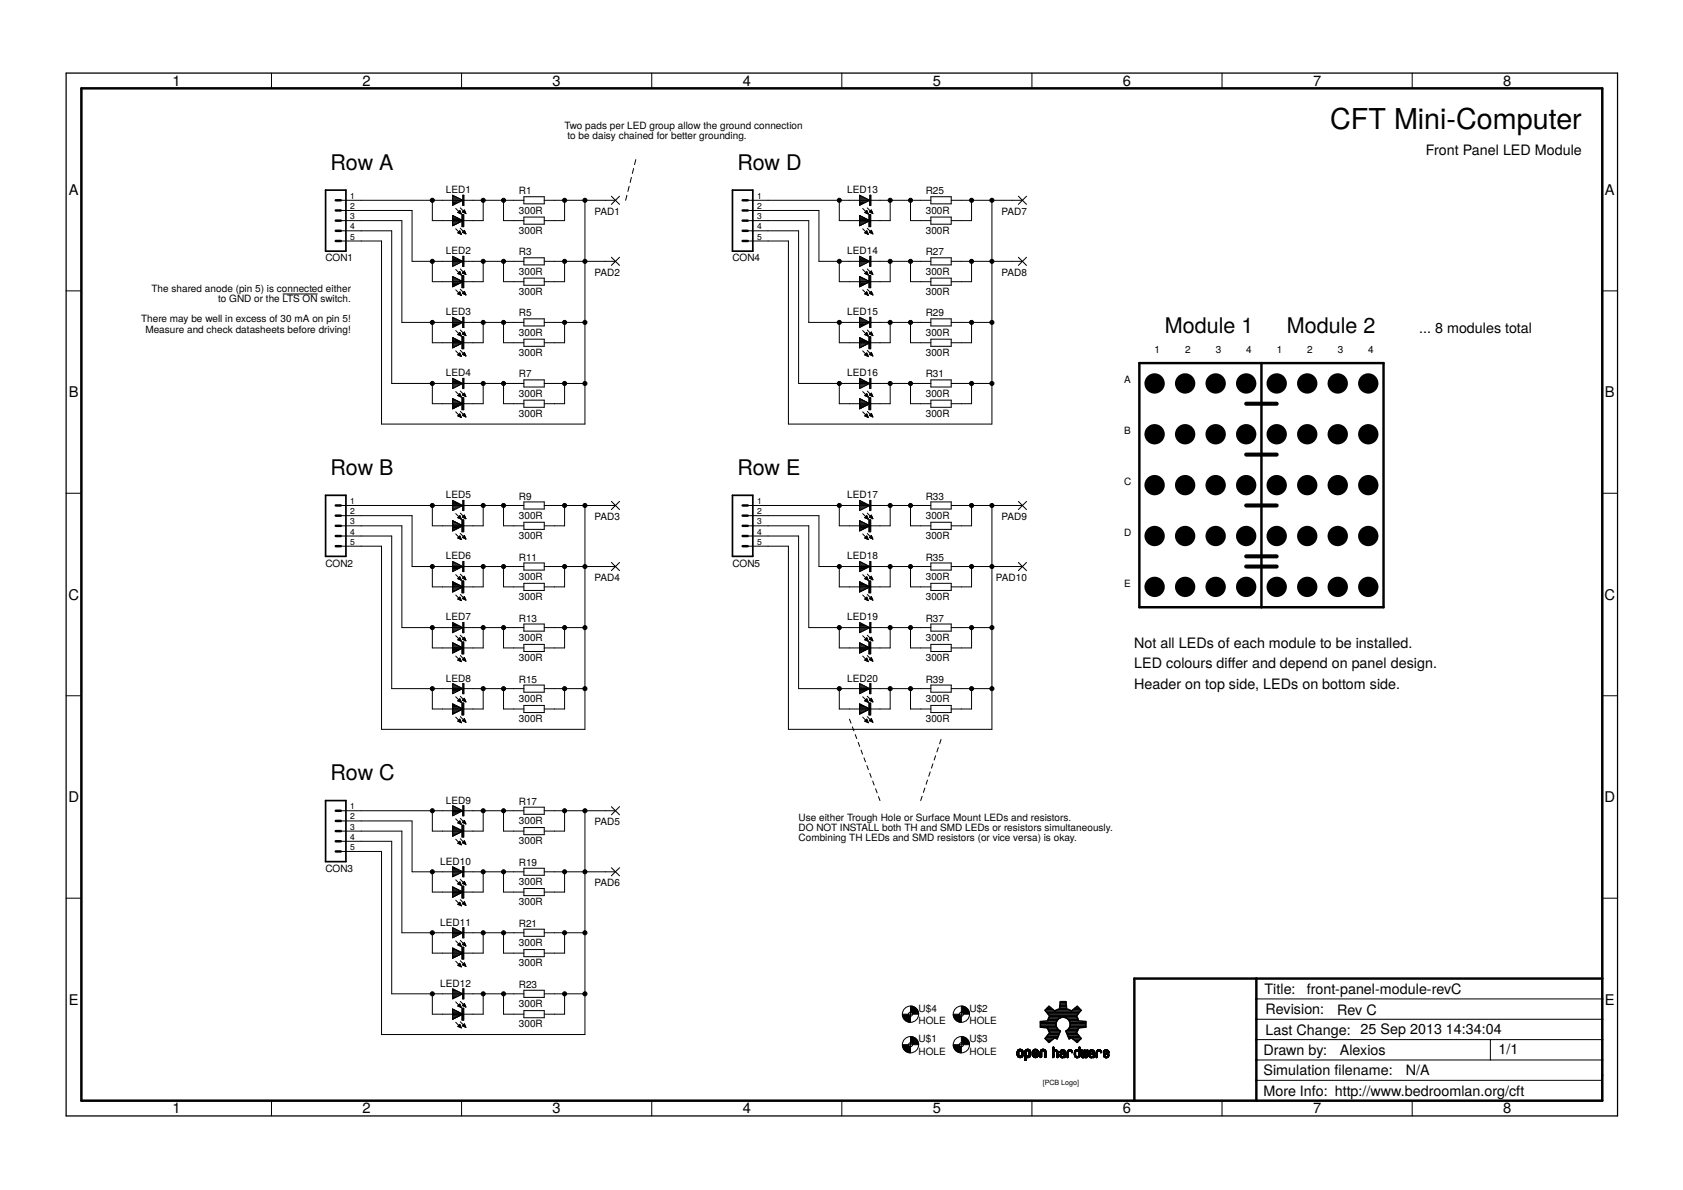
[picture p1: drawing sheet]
<svg xmlns="http://www.w3.org/2000/svg" width="420mm" height="297mm" viewBox="0 0 420 297" stroke-linecap="round" stroke-linejoin="round" font-family="sans-serif">
<defs><g id="words">
<text font-size="7.2" x="332.1" y="32.2">CFT Mini-Computer</text>
<g font-size="5.4">
<text x="82.5" y="42.4">Row A</text>
<text x="184.1" y="42.4">Row D</text>
<text x="290.8" y="83">Module 1</text>
<text x="321.3" y="83">Module 2</text>
<text x="82.5" y="118.6">Row B</text>
<text x="184.1" y="118.6">Row E</text>
<text x="82.5" y="194.7">Row C</text>
</g>
<g font-size="3.7">
<text x="43" y="21.4">1</text>
<text x="90.5" y="21.4">2</text>
<text x="138" y="21.4">3</text>
<text x="185.4" y="21.4">4</text>
<text x="232.9" y="21.4">5</text>
<text x="280.3" y="21.4">6</text>
<text x="327.8" y="21.4">7</text>
<text x="375.3" y="21.4">8</text>
<text x="17.2" y="48.6">A</text>
<text x="400.7" y="48.6">A</text>
<text x="17.2" y="99.2">B</text>
<text x="400.7" y="99.2">B</text>
<text x="17.1" y="149.7">C</text>
<text x="400.6" y="149.7">C</text>
<text x="17.1" y="200.2">D</text>
<text x="400.6" y="200.2">D</text>
<text x="17.2" y="250.8">E</text>
<text x="400.7" y="250.8">E</text>
<text x="43" y="277.9">1</text>
<text x="90.5" y="277.9">2</text>
<text x="138" y="277.9">3</text>
<text x="185.4" y="277.9">4</text>
<text x="232.9" y="277.9">5</text>
<text x="280.3" y="277.9">6</text>
<text x="327.8" y="277.9">7</text>
<text x="375.3" y="277.9">8</text>
</g>
<g font-size="3.6">
<text x="356" y="38.6">Front Panel LED Module</text>
<text x="354.3" y="83">... 8 modules total</text>
<text x="283.2" y="161.7">Not all LEDs of each module to be installed.</text>
<text x="283.2" y="166.8">LED colours difer and depend on panel design.</text>
<text x="306.5" y="166.8">f</text>
<text x="283.2" y="171.9">Header on top side, LEDs on bottom side.</text>
<text x="315.7" y="248.1">Title:</text>
<text x="326.2" y="248.2">front-panel-module-revC</text>
<text x="315.9" y="253.2">Revision:</text>
<text x="333.8" y="253.3">Rev C</text>
<text x="315.4" y="263.3">Drawn by:</text>
<text x="315.9" y="258.2">Last Change: 25 Sep 2013</text>
<text x="334.5" y="263.3">Alexios</text>
<text x="361" y="258.1">14:34:04</text>
<text x="374.1" y="263.2">1/1</text>
<text x="315.4" y="268.4">Simulation flename:</text>
<text x="333.2" y="268.4">i</text>
<text x="351" y="268.4">N/A</text>
<text x="315.4" y="273.5">More Info: http://www.bedroomlan.org/cft</text>
</g>
<g font-size="2.5">
<text x="141" y="32.2">Two pads per LED group allow the ground connection</text>
<text x="141.7" y="34.8">to be daisy chained for better grounding.</text>
<text x="111.3" y="48.2">LED1</text>
<text x="129.5" y="53.3">300R</text>
<text x="129.5" y="48.5">R1</text>
<text x="148.4" y="53.6">PAD1</text>
<text x="211.5" y="48.2">LED13</text>
<text x="231.1" y="53.3">300R</text>
<text x="231.1" y="48.5">R25</text>
<text x="250" y="53.6">PAD7</text>
<text x="129.5" y="58.4">300R</text>
<text x="231.1" y="58.4">300R</text>
<text x="81.3" y="65.2">CON1</text>
<text x="111.3" y="63.5">LED2</text>
<text x="129.5" y="63.7">R3</text>
<text x="182.9" y="65.2">CON4</text>
<text x="211.5" y="63.5">LED14</text>
<text x="231.1" y="63.7">R27</text>
<text x="129.5" y="68.5">300R</text>
<text x="148.4" y="68.9">PAD2</text>
<text x="231.1" y="68.5">300R</text>
<text x="250" y="68.9">PAD8</text>
<text x="37.8" y="72.8">The shared anode (pin 5) is connected either</text>
<text x="54.5" y="75.4">to GND or the LTS ON switch.</text>
<text x="129.5" y="73.6">300R</text>
<text x="231.1" y="73.6">300R</text>
<text x="35.2" y="80.5">There may be well in excess of 30 mA on pin 5!</text>
<text x="36.3" y="83">Measure and check datasheets before driving!</text>
<text x="111.3" y="78.7">LED3</text>
<text x="129.5" y="83.8">300R</text>
<text x="129.5" y="79">R5</text>
<text x="211.5" y="78.7">LED15</text>
<text x="231.1" y="83.8">300R</text>
<text x="231.1" y="79">R29</text>
<text x="129.5" y="88.8">300R</text>
<text x="231.1" y="88.8">300R</text>
<text x="288.3" y="88.1">1</text>
<text x="295.9" y="88.1">2</text>
<text x="303.5" y="88.1">3</text>
<text x="311.1" y="88.1">4</text>
<text x="318.7" y="88.1">1</text>
<text x="326.4" y="88.1">2</text>
<text x="334" y="88.1">3</text>
<text x="341.6" y="88.1">4</text>
<text x="111.3" y="93.9">LED4</text>
<text x="129.5" y="94.2">R7</text>
<text x="211.5" y="93.9">LED16</text>
<text x="231.1" y="94.2">R31</text>
<text x="280.6" y="95.7">A</text>
<text x="129.5" y="99">300R</text>
<text x="231.1" y="99">300R</text>
<text x="129.5" y="104.1">300R</text>
<text x="231.1" y="104.1">300R</text>
<text x="280.6" y="108.4">B</text>
<text x="111.3" y="124.4">LED5</text>
<text x="129.5" y="124.7">R9</text>
<text x="211.5" y="124.4">LED17</text>
<text x="231.1" y="124.7">R33</text>
<text x="280.6" y="121.1">C</text>
<text x="129.5" y="129.5">300R</text>
<text x="148.4" y="129.8">PAD3</text>
<text x="231.1" y="129.5">300R</text>
<text x="250" y="129.8">PAD9</text>
<text x="129.5" y="134.6">300R</text>
<text x="231.1" y="134.6">300R</text>
<text x="280.6" y="133.8">D</text>
<text x="81.3" y="141.4">CON2</text>
<text x="111.3" y="139.6">LED6</text>
<text x="129.5" y="139.9">R11</text>
<text x="182.9" y="141.4">CON5</text>
<text x="211.5" y="139.6">LED18</text>
<text x="231.1" y="139.9">R35</text>
<text x="129.5" y="144.7">300R</text>
<text x="129.5" y="149.8">300R</text>
<text x="148.4" y="145">PAD4</text>
<text x="231.1" y="144.7">300R</text>
<text x="231.1" y="149.8">300R</text>
<text x="248.6" y="145">PAD10</text>
<text x="280.6" y="146.5">E</text>
<text x="111.3" y="154.9">LED7</text>
<text x="129.5" y="155.2">R13</text>
<text x="211.5" y="154.9">LED19</text>
<text x="231.1" y="155.2">R37</text>
<text x="129.5" y="160">300R</text>
<text x="231.1" y="160">300R</text>
<text x="129.5" y="165">300R</text>
<text x="231.1" y="165">300R</text>
<text x="111.3" y="170.1">LED8</text>
<text x="129.5" y="170.4">R15</text>
<text x="211.5" y="170.1">LED20</text>
<text x="231.1" y="170.4">R39</text>
<text x="129.5" y="175.2">300R</text>
<text x="231.1" y="175.2">300R</text>
<text x="129.5" y="180.3">300R</text>
<text x="231.1" y="180.3">300R</text>
<text x="111.3" y="200.6">LED9</text>
<text x="129.5" y="200.9">R17</text>
<text x="129.5" y="205.7">300R</text>
<text x="148.4" y="206">PAD5</text>
<text x="199.4" y="204.9">Use either Trough Hole or Surface Mount LEDs and resistors.</text>
<text x="199.4" y="207.4">DO NOT INSTALL both TH and SMD LEDs or resistors simultaneously.</text>
<text x="199.4" y="210">Combining TH LEDs and SMD resistors (or vice versa) is okay.</text>
<text x="109.9" y="215.8">LED10</text>
<text x="129.5" y="210.7">300R</text>
<text x="81.3" y="217.6">CON3</text>
<text x="129.5" y="220.9">300R</text>
<text x="129.5" y="216.1">R19</text>
<text x="148.4" y="221.2">PAD6</text>
<text x="129.5" y="226">300R</text>
<text x="109.9" y="231.1">LED11</text>
<text x="129.5" y="231.3">R21</text>
<text x="129.5" y="236.1">300R</text>
<text x="129.5" y="241.2">300R</text>
<text x="109.9" y="246.3">LED12</text>
<text x="129.5" y="251.4">300R</text>
<text x="129.5" y="246.6">R23</text>
<text x="129.5" y="256.5">300R</text>
<text x="229.3" y="255.6">HOLE</text>
<text x="229.3" y="252.6">U$4</text>
<text x="242" y="255.6">HOLE</text>
<text x="242" y="252.6">U$2</text>
<text x="229.3" y="263.2">HOLE</text>
<text x="229.3" y="260.2">U$1</text>
<text x="242" y="263.2">HOLE</text>
<text x="242" y="260.2">U$3</text>
</g>
<g font-size="2.1">
<text x="87.4" y="49.6">1</text>
<text x="87.4" y="52.2">2</text>
<text x="189" y="49.6">1</text>
<text x="189" y="52.2">2</text>
<text x="87.4" y="54.7">3</text>
<text x="87.4" y="57.3">4</text>
<text x="87.4" y="59.8">5</text>
<text x="189" y="54.7">3</text>
<text x="189" y="57.3">4</text>
<text x="189" y="59.8">5</text>
<text x="87.4" y="125.8">1</text>
<text x="189" y="125.8">1</text>
<text x="87.4" y="128.4">2</text>
<text x="87.4" y="130.9">3</text>
<text x="189" y="128.4">2</text>
<text x="189" y="130.9">3</text>
<text x="87.4" y="133.4">4</text>
<text x="87.4" y="136">5</text>
<text x="189" y="133.4">4</text>
<text x="189" y="136">5</text>
<text x="87.4" y="202">1</text>
<text x="87.4" y="204.6">2</text>
<text x="87.4" y="207.1">3</text>
<text x="87.4" y="209.6">4</text>
<text x="87.4" y="212.2">5</text>
</g>
<text font-size="1.8" x="260.3" y="270.9">[PCB Logo]</text>
</g></defs>
<path d="M311.1 100.8h7.6M311.1 113.5h7.6M311.1 126.2h7.6M311.1 138.9h7.6M311.1 141.4h7.6" fill="none" stroke="#000" stroke-width="1"/>
<g fill="none" stroke="#000" stroke-width=".25">
<path d="M67.8 18.2v3.9M115.2 18.2v3.9M162.7 18.2v3.9M210.2 18.2v3.9M257.6 18.2v3.9M305.1 18.2v3.9M352.6 18.2v3.9M20.3 22.1h379.7v252.6h-379.7zM158.7 39.8l-.3 1.3M85.1 50h45.7M85.1 55.1h15.2v25.4h30.5M85.1 52.5h17.8v12.7h27.9"/>
<path d="M85.1 57.6h12.7v38.1h33M107.9 50v5.1h12.7v-5.1M113 48.7l2.5 1.3-2.5 1.3zM113 53.8l2.5 1.3-2.5 1.2zM113 51.2h.1M113 51h.5M113 50.8h1M113 50.6h1.4M113 50.4h1.9M113 50.1h2.3M113 49.9h2.4M113 49.7h1.9"/>
<path d="M113 49.5h1.5M113 49.2h1M113 49h.6M113 48.8h.2M113 56.1h.5M113 55.9h.9M113 55.7h1.3M113 55.5h1.8M113 55.2h2.2M113 55h2.4M113 54.8h2M113 54.6h1.6"/>
<path d="M113 54.4h1.1M113 54.1h.7M113 53.9h.2M113.8 52l1.4 1.4M113.8 57.1l1.4 1.4M114.3 53l.5-.5 .4 .9zM114.3 58.1l.5-.5 .4 .9zM114.3 53h.7M114.4 58.1h.6M114.4 58.2h.6M114.4 53.1h.6M114.5 52.9h.4"/>
<path d="M114.5 57.9h.4M114.6 52.7h.3M114.6 57.8h.3M114.7 58.3h.4M114.7 52.6h.1M114.7 53.2h.4M114.7 57.7h.1M114.9 51.9l1.4 1.4M114.9 57l1.4 1.4M115 58.4h.1M115 53.3h.1M115.4 52.9l.5-.5 .4 .9z"/>
<path d="M115.4 58l.5-.5 .4 .9zM115.5 52.9h.6M115.5 57.9h.6M115.5 48.7h.3v2.5l-.3 .1zM115.5 53.8v2.5M115.5 51h.3M115.5 50.8h.3M115.5 50.6h.3M115.5 50.4h.3M115.5 50.1h.3M115.5 49.9h.3M115.5 49.7h.3"/>
<path d="M115.5 49.5h.3M115.5 49.2h.3M115.5 49h.3M115.5 48.8h.3M115.6 58.1h.6M115.6 53h.6M115.6 52.7h.5M115.6 57.8h.5M115.7 52.6h.3M115.7 57.7h.3M115.8 52.5h.2M115.8 58.2h.4"/>
<path d="M115.9 53.1h.3M115.9 57.6h.1M116.1 58.3h.2M116.2 53.2h.1M125.7 50v5.1h5.1M130.8 49.1h5.1v1.8h-5.1zM130.8 54.2h5.1v1.8h-5.1zM135.9 50h17.7M140.9 50v5.1h-5M146 50v55.9h-50.8v-45.7h-10.1M152.6 49l2.1 2M154.7 49l-2.1 2"/>
<path d="M156.5 48.7l-.3 1.3M157.1 46.5l-.3 1.3M157.6 44.3l-.3 1.3M158.2 42.1l-.3 1.2M186.7 50h45.7M186.7 55.1h15.2v25.4h30.5M186.7 52.5h17.7v12.7h28M186.7 57.6h12.7v38.1h33M209.5 50v5.1h12.7v-5.1M214.6 51.2h.1M214.6 51h.5M214.6 50.8h1"/>
<path d="M214.6 50.6h1.4M214.6 50.4h1.9M214.6 50.1h2.3M214.6 49.9h2.4M214.6 49.7h1.9M214.6 49.5h1.5M214.6 49.2h1M214.6 49h.6M214.6 48.8h.1M214.6 48.7l2.5 1.3-2.5 1.3zM214.6 53.8l2.5 1.3-2.5 1.2zM214.6 56.1h.5"/>
<path d="M214.6 55.9h.9M214.6 55.7h1.3M214.6 55.5h1.8M214.6 55.2h2.2M214.6 55h2.4M214.6 54.8h2M214.6 54.6h1.5M214.6 54.4h1.1M214.6 54.1h.6M214.6 53.9h.2M215.4 52l1.4 1.4M215.4 57.1l1.4 1.4"/>
<path d="M215.9 53l.5-.5 .4 .9zM215.9 58.1l.5-.5 .4 .9zM215.9 53h.7M215.9 58.1h.7M216 58.2h.6M216 53.1h.6M216 52.9h.5M216.1 57.9h.4M216.2 52.7h.3M216.2 57.8h.3M216.3 58.3h.4M216.3 53.2h.4"/>
<path d="M216.3 52.6h.1M216.3 57.7h.1M216.5 51.9l1.4 1.4M216.5 57l1.4 1.4M216.6 58.4h.1M216.6 53.3h.1M217 58l.5-.5 .4 .9zM217 52.9l.5-.5 .4 .9zM217.1 52.9h.6M217.1 57.9h.6M217.1 48.7h.3v2.5h-.3zM217.1 51h.3"/>
<path d="M217.1 50.8h.3M217.1 50.6h.3M217.1 50.4h.3M217.1 50.1h.3M217.1 49.9h.3M217.1 49.7h.3M217.1 49.5h.3M217.1 49.2h.3M217.1 49h.3M217.1 48.8h.3M217.1 53.8v2.5M217.1 58.1h.7"/>
<path d="M217.2 53h.6M217.2 52.7h.5M217.2 57.8h.5M217.3 52.6h.3M217.3 57.7h.3M217.4 52.5h.2M217.4 58.2h.4M217.4 57.6h.2M217.5 53.1h.3M217.7 58.3h.2M217.7 53.2h.2M227.3 50v5.1h5.1"/>
<path d="M232.4 49.1h5.1v1.8h-5.1zM232.4 54.2h5.1v1.8h-5.1zM237.5 50h17.7M242.5 50v5.1h-5M247.6 50v55.9h-50.8v-45.7h-10.1M254.2 49l2.1 2M256.3 49l-2.1 2M16.5 72.6h3.8M70.6 73.4h8.7M107.9 65.2v5.1h12.7v-5.1M113 64l2.5 1.2-2.5 1.3zM113 69l2.5 1.3-2.5 1.3z"/>
<path d="M113 79.2l2.5 1.3-2.5 1.2zM113 66.1h.8M113 64.3h.8M113 66.3h.3M113 65.9h1.2M113 65.7h1.7M113 65.4h2.1M113 65h2.1M113 64.8h1.7M113 64.6h1.2M113 64.1h.3M113 71.2h.7"/>
<path d="M113 79.9h1.4M113 79.7h1M113 79.5h.5M113 79.2h.1M113 71.5h.3M113 71h1.2M113 70.8h1.6M113 70.6h2M113 70.1h2.2M113 69.9h1.7M113 69.7h1.3M113 69.4h.9"/>
<path d="M113 69.2h.4M113.8 67.3l1.4 1.4M113.8 72.3l1.4 1.4M114.3 68.3l.5-.5 .4 .9zM114.3 73.4l.5-.5 .4 .8zM114.3 73.4h.7M114.3 68.3h.7M114.4 68.2h.6M114.4 73.3h.6M114.5 68.1h.4M114.5 73.1h.4M114.6 73.5h.5"/>
<path d="M114.6 68.4h.5M114.6 67.9h.3M114.6 73h.3M114.7 67.8h.1M114.8 72.9h.1M114.9 73.6h.2M114.9 67.1l1.4 1.4M114.9 68.5h.2M114.9 72.2l1.4 1.4M115.2 73.7h.1M115.4 68.2l.5-.6 .4 .9zM115.4 73.2l.5-.5 .4 .9z"/>
<path d="M115.5 73.3h.7M115.5 68.2h.7M115.5 68.1h.6M115.5 73.1h.6M115.5 64h.3v2.5h-.3zM115.5 69v2.6M115.5 79.2h.3v2.5h-.3zM115.5 66.1h.3M115.5 64.3h.3M115.5 66.3h.3M115.5 65.9h.3M115.5 65.7h.3"/>
<path d="M115.5 65.4h.3M115.5 65h.3M115.5 64.8h.3M115.5 64.6h.3M115.5 64.1h.3M115.5 79.9h.3M115.5 79.7h.3M115.5 79.5h.3M115.6 67.9h.5M115.7 73h.4M115.8 67.8h.2M115.8 73.4h.4"/>
<path d="M115.8 68.3h.4M115.8 72.9h.2M115.9 67.7h.1M115.9 72.8h.1M116 73.5h.3M116.1 68.4h.2M116.3 73.6h.1M125.7 65.2v5.1h5.1M130.8 64.3h5.1v1.8h-5.1zM130.8 69.4h5.1v1.8h-5.1zM130.8 79.6h5.1v1.8h-5.1zM135.9 65.2h17.7"/>
<path d="M140.9 65.2v5.1h-5M152.6 64.2l2.1 2.1M154.7 64.2l-2.1 2.1M209.5 65.2v5.1h12.7v-5.1M214.6 66.1h.8M214.6 64.3h.8M214.6 66.3h.3M214.6 65.9h1.2M214.6 65.7h1.7M214.6 65.4h2.1M214.6 65h2.1M214.6 64.8h1.7"/>
<path d="M214.6 64.6h1.2M214.6 64.1h.3M214.6 71.2h.7M214.6 79.9h1.4M214.6 79.7h1M214.6 79.5h.5M214.6 79.2h.1M214.6 64l2.5 1.2-2.5 1.3zM214.6 69l2.5 1.3-2.5 1.3zM214.6 79.2l2.5 1.3-2.5 1.2zM214.6 71.5h.3M214.6 71h1.2"/>
<path d="M214.6 70.8h1.6M214.6 70.6h2M214.6 70.1h2.2M214.6 69.9h1.7M214.6 69.7h1.3M214.6 69.4h.8M214.6 69.2h.4M215.4 67.3l1.4 1.4M215.4 72.3l1.4 1.4M215.9 73.4l.5-.5 .4 .8M215.9 68.3l.5-.5 .4 .9zM215.9 73.4l.9 .3"/>
<path d="M215.9 73.4h.7M215.9 68.3h.7M216 68.2h.6M216 73.3h.6M216.1 68.1h.4M216.1 73.1h.4M216.2 73.5h.5M216.2 68.4h.5M216.2 67.9h.3M216.2 73h.3M216.3 67.8h.1M216.3 72.9h.1"/>
<path d="M216.5 73.6h.2M216.5 68.5h.2M216.5 67.1l1.4 1.4M216.5 72.2l1.4 1.4M216.7 73.7h.1M217 68.2l.5-.6 .4 .9zM217 73.2l.5-.5 .4 .9zM217.1 73.3h.7M217.1 68.2h.7M217.1 68.1h.6M217.1 73.1h.6M217.1 66.1h.3"/>
<path d="M217.1 64.3h.3M217.1 66.3h.3M217.1 65.9h.3M217.1 65.7h.3M217.1 65.4h.3M217.1 65h.3M217.1 64.8h.3M217.1 64.6h.3M217.1 64.1h.3M217.1 64h.3v2.5h-.3zM217.1 79.9h.3M217.1 79.7h.3"/>
<path d="M217.1 79.5h.3M217.1 79.2h.3v2.5h-.3zM217.1 69v2.6M217.2 67.9h.5M217.2 73h.5M217.3 73.4h.5M217.4 67.8h.2M217.4 72.9h.2M217.4 68.3h.4M217.5 67.7h.1M217.5 72.8h.1M217.6 73.5h.2"/>
<path d="M217.7 68.4h.2M217.9 73.6h.1M227.3 65.2v5.1h5.1M232.4 64.3h5.1v1.8h-5.1zM232.4 69.4h5.1v1.8h-5.1zM232.4 79.6h5.1v1.8h-5.1zM237.5 65.2h17.7M242.5 65.2v5.1h-5M254.2 64.2l2.1 2.1M256.3 64.2l-2.1 2.1M400 72.6h3.8M107.9 80.5v5.1h12.7v-5.1"/>
<path d="M107.9 95.7v5.1h12.7v-5.1M113 84.3l2.5 1.3-2.5 1.2zM113 94.4l2.5 1.3-2.5 1.3zM113 99.5l2.5 1.3-2.5 1.2zM113 81.7h.1M113 81.4h.6M113 81.2h1M113 81h1.5M113 80.8h1.9M113 80.6h2.4M113 80.3h2.3M113 80.1h1.9"/>
<path d="M113 94.8h.7M113 96.8h.4M113 96.6h.8M113 96.4h1.3M113 96.1h1.7M113 95.9h2.2M113 95.7h2.8M113 95.5h2.1M113 95.2h1.6M113 95h1.2M113 94.6h.3M113 86.8h.1"/>
<path d="M113 86.6h.5M113 86.3h1M113 86.1h1.4M113 85.9h1.9M113 85.7h2.3M113 85.4h2.4M113 85.2h1.9M113 85h1.5M113 84.8h1M113 84.6h.6M113 84.3h.2M113 99.9h.8"/>
<path d="M113 99.7h.3M113.8 82.5l1.4 1.4M113.8 97.7l1.4 1.4M113.8 87.6l1.4 1.4M114.3 83.5l.9 .4M114.3 98.7l.5-.4 .4 .8zM114.3 88.6l.5-.5 .4 .9zM114.3 83.5h.7M114.3 88.6h.7M114.3 98.7h.7M114.4 83.4h.6M114.4 88.5h.6"/>
<path d="M114.4 98.8h.6M114.5 98.6h.4M114.5 88.7h.6M114.5 83.6h.6M114.6 83.3h.3M114.6 88.3h.3M114.6 98.5h.3M114.7 83.1h.2M114.7 88.2h.2M114.7 98.3h.1M114.7 98.9h.4M114.8 83l-.5 .5"/>
<path d="M114.8 83l.4 .9M114.8 83h.1M114.8 88.8h.3M114.8 83.7h.3M114.9 82.4l1.4 1.4M114.9 97.6l1.4 1.4M114.9 87.5l1.4 1.4M115 99.1h.1M115.1 88.9h.1M115.1 83.9h.1M115.4 98.6l.5-.5 .4 .9zM115.4 83.4h.8"/>
<path d="M115.4 88.5h.7M115.5 98.6h.6M115.5 84.3v2.5M115.5 94.4h.3v2.6h-.3zM115.5 99.5v2.5M115.5 81.7h.3M115.5 81.4h.3M115.5 81.2h.3M115.5 81h.3M115.5 80.8h.3M115.5 80.6h.3M115.5 80.3h.3"/>
<path d="M115.5 80.1h.3M115.5 94.8h.3M115.5 96.8h.3M115.5 96.6h.3M115.5 96.4h.3M115.5 96.1h.3M115.5 95.9h.3M115.5 95.5h.3M115.5 95.2h.3M115.5 95h.3M115.5 94.6h.3M115.6 83.3h.5"/>
<path d="M115.6 88.3h.5M115.6 98.5h.5M115.6 98.7h.6M115.7 88.6h.5M115.7 83.1h.4M115.7 83.5h.5M115.7 88.2h.3M115.7 98.3h.3M115.8 83h.2M115.8 88.1h.2M115.8 98.2h.2M115.9 98.8h.3"/>
<path d="M115.9 82.9l-.5 .5 .9 .4M115.9 82.9l.4 .9M115.9 82.9h.1M115.9 88l-.5 .5 .9 .4M115.9 88l.4 .9M115.9 88h.1M116 88.7h.2M116 83.6h.2M116.2 98.9h.1M116.2 88.8h.1M116.2 83.7h.1M125.7 80.5v5.1h5.1"/>
<path d="M125.7 95.7v5.1h5.1M130.8 84.7h5.1v1.7h-5.1zM130.8 94.8h5.1v1.8h-5.1zM130.8 99.9h5.1v1.8h-5.1zM135.9 80.5h10.1M135.9 95.7h10.1M140.9 80.5v5.1h-5M140.9 95.7v5.1h-5M209.5 80.5v5.1h12.7v-5.1M209.5 95.7v5.1h12.7v-5.1M214.6 81.7h.1M214.6 81.4h.6"/>
<path d="M214.6 81.2h1M214.6 81h1.5M214.6 80.8h1.9M214.6 80.6h2.4M214.6 80.3h2.3M214.6 80.1h1.9M214.6 94.8h.7M214.6 96.8h.4M214.6 96.6h.8M214.6 96.4h1.3M214.6 96.1h1.7M214.6 95.9h2.2"/>
<path d="M214.6 95.7h2.5M214.6 95.5h2M214.6 95.2h1.6M214.6 95h1.2M214.6 94.6h.3M214.6 84.3l2.5 1.3-2.5 1.2zM214.6 94.4l2.5 1.3-2.5 1.3zM214.6 99.5l2.5 1.3-2.5 1.2zM214.6 86.8h.1M214.6 86.6h.5M214.6 86.3h1M214.6 86.1h1.4"/>
<path d="M214.6 85.9h1.9M214.6 85.7h2.3M214.6 85.4h2.4M214.6 85.2h1.9M214.6 85h1.5M214.6 84.8h1M214.6 84.6h.6M214.6 84.3h.1M214.6 99.9h.8M214.6 99.7h.3M215.4 82.5l1.4 1.4M215.4 97.7l1.4 1.4"/>
<path d="M215.4 87.6l1.4 1.4M215.9 83.5l.9 .4M215.9 98.7l.5-.4 .4 .8zM215.9 88.6l.5-.5 .4 .9zM215.9 83.5h.7M215.9 88.6h.7M215.9 98.7h.7M216 83.4h.5M216 98.8h.6M216 88.5h.5M216 98.6h.5M216.1 88.7h.5"/>
<path d="M216.1 83.6h.5M216.1 83.3h.4M216.2 88.3h.3M216.2 98.5h.3M216.3 83.1h.2M216.3 88.2h.1M216.3 98.3h.1M216.3 98.9h.4M216.4 83h.1M216.4 83l-.5 .5M216.4 83l.4 .9M216.4 88.8h.3"/>
<path d="M216.4 83.7h.3M216.5 82.4l1.4 1.4M216.5 97.6l1.4 1.4M216.5 87.5l1.4 1.4M216.6 99.1h.1M216.7 88.9h.1M216.7 83.9h.1M217 83.4h.7M217 83.4l.9 .4M217 98.6l.5-.5 .4 .9zM217 88.5h.7M217.1 98.6h.6"/>
<path d="M217.1 83.3h.6M217.1 81.7h.3M217.1 81.4h.3M217.1 81.2h.3M217.1 81h.3M217.1 80.8h.3M217.1 80.6h.3M217.1 80.3h.3M217.1 80.1h.3M217.1 94.8h.3M217.1 96.8h.3M217.1 96.6h.3"/>
<path d="M217.1 96.4h.3M217.1 96.1h.3M217.1 95.9h.3M217.1 95.7h.3M217.1 95.5h.3M217.1 95.2h.3M217.1 95h.3M217.1 94.6h.3M217.1 94.4h.3v2.6h-.3zM217.1 84.3v2.5M217.1 99.5v2.5M217.2 88.3h.5"/>
<path d="M217.2 98.7h.6M217.2 98.5h.5M217.3 88.6h.5M217.3 83.5h.5M217.3 83.1h.3M217.3 88.2h.3M217.3 98.3h.3M217.4 83h.2M217.4 88.1h.2M217.4 98.2h.2M217.5 98.8h.3M217.5 82.9h.1"/>
<path d="M217.5 82.9l-.5 .5M217.5 82.9l.4 .9M217.5 88.7h.3M217.5 88h.1M217.5 88l-.5 .5 .9 .4M217.5 88l.4 .9M217.6 83.6h.2M217.8 98.9h.1M217.8 88.8h.1M217.8 83.7h.1M227.3 80.5v5.1h5.1M227.3 95.7v5.1h5.1"/>
<path d="M232.4 84.7h5.1v1.7h-5.1zM232.4 94.8h5.1v1.8h-5.1zM232.4 99.9h5.1v1.8h-5.1zM237.5 80.5h10.1M237.5 95.7h10.1M242.5 80.5v5.1h-5M242.5 95.7v5.1h-5M113 101.7h.8M113 101.9h.3M113 101.5h1.2M113 101.2h1.7M113 101h2.1"/>
<path d="M113 100.6h2.1M113 100.4h1.7M113 100.1h1.2M113.8 102.8l1.4 1.4M114.3 103.8l.5-.5 .4 .9zM114.4 103.8h.6M114.4 103.9h.6M114.5 103.7h.4M114.6 103.5h.3M114.7 104h.4M114.7 103.4h.1M114.9 102.7l1.4 1.4"/>
<path d="M115 104.1h.1M115.4 103.7l.5-.5 .4 .9zM115.5 103.7h.6M115.6 103.8h.6M115.6 103.5h.5M115.7 103.4h.3M115.8 103.3h.2M115.9 103.9h.3M116.1 104h.2M214.6 101.7h.8M214.6 101.9h.3M214.6 101.5h1.2"/>
<path d="M214.6 101.2h1.7M214.6 101h2.1M214.6 100.6h2.1M214.6 100.4h1.7M214.6 100.1h1.2M215.4 102.8l1.4 1.4M215.9 103.8l.5-.5 .4 .9zM215.9 103.8h.7M216 103.9h.6M216.1 103.7h.4M216.2 103.5h.3M216.3 104h.4"/>
<path d="M216.3 103.4h.1M216.5 102.7l1.4 1.4M216.6 104.1h.1M217 103.7l.5-.5 .4 .9zM217.1 103.7h.6M217.2 103.8h.6M217.2 103.5h.5M217.3 103.4h.3M217.4 103.9h.4M217.4 103.3h.2M217.7 104h.2M16.5 123.1h3.8"/>
<path d="M85.1 126.2h45.7M85.1 131.3h15.2v25.4h30.5M85.1 128.7h17.8v12.7h27.9M85.1 133.8h12.7v38.1h33M107.9 126.2v5.1h12.7v-5.1M113 124.9l2.5 1.3-2.5 1.2zM113 130l2.5 1.3-2.5 1.2zM113 127.2h.5M113 127h.9M113 126.8h1.3M113 126.6h1.8M113 126.3h2.2"/>
<path d="M113 126.1h2.4M113 125.9h2M113 125.7h1.6M113 125.5h1.1M113 125.2h.7M113 125h.2M113 132.1h.8M113 132.3h.4M113 131.9h1.3M113 131.7h1.7M113 131.4h2.2M113 131h2.1"/>
<path d="M113 130.8h1.6M113 130.6h1.2M113 130.3h.7M113 130.1h.3M113.8 128.2l1.4 1.4M113.8 133.3l1.4 1.4M114.3 129.2l.9 .4M114.3 129.2l.5-.5 .4 .9M114.3 134.3l.9 .4M114.3 129.2h.7M114.3 134.3h.7M114.4 129.1h.6"/>
<path d="M114.4 134.2h.6M114.5 134.4h.6M114.5 129h.4M114.6 129.3h.5M114.6 134h.3M114.7 128.9h.2M114.7 133.9h.2M114.8 128.7h.1M114.8 133.8l-.5 .5M114.8 133.8l.4 .9M114.8 133.8h.1M114.8 134.5h.3"/>
<path d="M114.8 129.5h.3M114.9 128.1l1.4 1.4M114.9 133.2l1.4 1.4M115.1 134.6h.1M115.1 129.6h.1M115.4 129.1l.5-.5 .4 .9zM115.4 129.1h.8M115.4 134.2h.7M115.5 124.9h.3v2.5h-.3zM115.5 130v2.5M115.5 129h.6M115.5 127.2h.3"/>
<path d="M115.5 127h.3M115.5 126.8h.3M115.5 126.6h.3M115.5 126.3h.3M115.5 126.1h.3M115.5 125.9h.3M115.5 125.7h.3M115.5 125.5h.3M115.5 125.2h.3M115.5 125h.3M115.6 134h.5M115.7 128.9h.4"/>
<path d="M115.7 134.3h.5M115.7 129.2h.5M115.7 133.9h.4M115.8 128.7h.2M115.8 133.8h.2M115.9 128.6h.1M115.9 133.7l-.5 .5 .9 .4M115.9 133.7l.4 .9M115.9 133.7h.1M116 134.4h.2M116 129.3h.3M116.2 134.5h.1"/>
<path d="M116.3 129.5h.1M125.7 126.2v5.1h5.1M130.8 125.3h5.1v1.8h-5.1zM130.8 130.4h5.1v1.7h-5.1zM135.9 126.2h17.7M140.9 126.2v5.1h-5M146 126.2v55.9h-50.8v-45.8h-10.1M152.6 125.2l2.1 2M154.7 125.2l-2.1 2M186.7 126.2h45.7M186.7 131.3h15.2v25.4h30.5M186.7 128.7h17.7v12.7h28"/>
<path d="M186.7 133.8h12.7v38.1h33M209.5 126.2v5.1h12.7v-5.1M214.6 127.2h.5M214.6 127h.9M214.6 126.8h1.3M214.6 126.6h1.8M214.6 126.3h2.2M214.6 126.1h2.4M214.6 125.9h2M214.6 125.7h1.5M214.6 125.5h1.1M214.6 125.2h.6"/>
<path d="M214.6 125h.2M214.6 132.1h.8M214.6 124.9l2.5 1.3-2.5 1.2zM214.6 130l2.5 1.3-2.5 1.2zM214.6 132.3h.4M214.6 131.9h1.3M214.6 131.7h1.7M214.6 131.4h2.2M214.6 131h2M214.6 130.8h1.6M214.6 130.6h1.2M214.6 130.3h.7"/>
<path d="M214.6 130.1h.3M215.4 128.2l1.4 1.4M215.4 133.3l1.4 1.4M215.9 129.2h.7M215.9 129.2l.9 .4M215.9 129.2l.5-.5 .4 .9M215.9 134.3l.9 .4M215.9 134.3h.7M216 129.1h.6M216 134.2h.5M216.1 134.4h.5M216.1 129.3h.5"/>
<path d="M216.1 129h.4M216.1 134h.4M216.2 128.9h.3M216.3 133.9h.1M216.4 128.7h.1M216.4 134.5h.3M216.4 133.8h.1M216.4 133.8l-.5 .5M216.4 133.8l.4 .9M216.4 129.5h.3M216.5 128.1l1.4 1.4M216.5 133.2l1.4 1.4"/>
<path d="M216.7 134.6h.1M216.7 129.6h.1M217 129.1h.7M217 129.1l.9 .4M217 129.1l.5-.5 .4 .9M217 134.2h.7M217.1 129h.6M217.1 127.2h.3M217.1 127h.3M217.1 126.8h.3M217.1 126.6h.3M217.1 126.3h.3"/>
<path d="M217.1 126.1h.3M217.1 125.9h.3M217.1 125.7h.3M217.1 125.5h.3M217.1 125.2h.3M217.1 125h.3M217.1 124.9h.3v2.5h-.3zM217.1 130v2.5M217.1 134h.6M217.3 128.9h.3M217.3 134.3h.5M217.3 133.9h.3"/>
<path d="M217.3 129.2h.5M217.4 128.7h.2M217.4 133.8h.2M217.5 128.6h.1M217.5 133.7h.1M217.5 133.7l-.5 .5 .9 .4M217.5 133.7l.4 .9M217.6 134.4h.2M217.6 129.3h.2M217.8 134.5h.1M217.8 129.5h.1M227.3 126.2v5.1h5.1"/>
<path d="M232.4 125.3h5.1v1.8h-5.1zM232.4 130.4h5.1v1.7h-5.1zM237.5 126.2h17.7M242.5 126.2v5.1h-5M247.6 126.2v55.9h-50.8v-45.8h-10.1M254.2 125.2l2.1 2M256.3 125.2l-2.1 2M400 123.1h3.8M107.9 141.4v5.1h12.7v-5.1M107.9 156.7v5h12.7v-5M113 140.1l2.5 1.3-2.5 1.3zM113 145.2l2.5 1.3-2.5 1.3z"/>
<path d="M113 155.4l2.5 1.3-2.5 1.2zM113 140.6h.9M113 142.6h.3M113 142.3h.7M113 142.1h1.2M113 141.9h1.6M113 141.7h2M113 141.2h2.2M113 141h1.7M113 140.8h1.3M113 140.3h.4M113 157.9h.1"/>
<path d="M113 157.7h.5M113 157.5h1M113 157.2h1.4M113 157h1.9M113 156.8h2.3M113 156.6h2.4M113 156.3h1.9M113 156.1h1.5M113 155.9h1M113 155.7h.6M113 155.4h.2M113 147.7h.2"/>
<path d="M113 147.4h.6M113 147.2h1.1M113 147h1.5M113 146.8h2M113 146.6h2.4M113 146.3h2.3M113 146.1h1.8M113 145.9h1.4M113 145.7h.9M113 145.5h.5M113 145.2h.1M113.8 143.4l1.4 1.4"/>
<path d="M113.8 158.7l1.4 1.4M113.8 148.5l1.4 1.4M114.3 144.5l.5-.5 .4 .8zM114.3 159.7l.5-.5 .4 .9zM114.3 149.5l.5-.5 .4 .9zM114.3 144.4h.7M114.3 149.5h.7M114.4 159.7h.6M114.4 159.6h.6M114.4 149.6h.6M114.4 144.3h.5M114.5 144.5h.5"/>
<path d="M114.5 149.4h.4M114.5 159.5h.4M114.6 144.2h.3M114.6 149.2h.3M114.6 159.4h.3M114.7 159.9h.4M114.7 144.1h.1M114.7 149.7h.4M114.7 149.1h.1M114.7 144.7h.4M114.7 159.3h.1M114.9 143.3l1.4 1.4"/>
<path d="M114.9 158.6l1.4 1.4M114.9 148.4l1.4 1.4M114.9 160h.2M115 149.8h.1M115 144.8h.1M115.4 144.3l.5-.5 .4 .9zM115.4 159.6l.5-.5 .4 .9zM115.4 149.4l.5-.5 .4 .9zM115.5 144.3h.6M115.5 149.4h.6M115.5 159.5h.6M115.5 159.6h.7"/>
<path d="M115.5 140.1h.3v2.6h-.3zM115.5 145.2v2.6M115.5 155.4h.3v2.5h-.3zM115.5 140.6h.3M115.5 142.6h.3M115.5 142.3h.3M115.5 142.1h.3M115.5 141.9h.3M115.5 141.7h.3M115.5 141.2h.3M115.5 141h.3M115.5 140.8h.3"/>
<path d="M115.5 140.3h.3M115.5 157.7h.3M115.5 157.5h.3M115.5 157.2h.3M115.5 157h.3M115.5 156.8h.3M115.5 156.6h.3M115.5 156.3h.3M115.5 156.1h.3M115.5 155.9h.3M115.5 155.7h.3M115.5 155.4h.3"/>
<path d="M115.6 144.2h.5M115.6 149.5h.6M115.6 144.4h.6M115.6 149.2h.5M115.6 159.4h.5M115.7 144.1h.3M115.7 149.1h.3M115.8 159.3h.2M115.8 159.7h.4M115.8 143.9h.2M115.8 149h.2M115.9 159.1h.1"/>
<path d="M115.9 149.6h.3M115.9 144.5h.3M116.1 159.9h.2M116.1 149.7h.2M116.2 144.7h.1M125.7 141.4v5.1h5.1M125.7 156.7v5h5.1M130.8 140.5h5.1v1.8h-5.1zM130.8 145.6h5.1v1.8h-5.1zM130.8 155.8h5.1v1.7h-5.1zM135.9 141.4h17.7M135.9 156.7h10.1"/>
<path d="M140.9 141.4v5.1h-5M140.9 156.7v5h-5M152.6 140.4l2.1 2M154.7 140.4l-2.1 2M209.5 141.4v5.1h12.7v-5.1M209.5 156.7v5h12.7v-5M214.6 140.6h.8M214.6 142.6h.3M214.6 142.3h.7M214.6 142.1h1.2M214.6 141.9h1.6M214.6 141.7h2"/>
<path d="M214.6 141.2h2.2M214.6 141h1.7M214.6 140.8h1.3M214.6 140.3h.4M214.6 157.9h.1M214.6 157.7h.5M214.6 157.5h1M214.6 157.2h1.4M214.6 157h1.9M214.6 156.8h2.3M214.6 156.6h2.4M214.6 156.3h1.9"/>
<path d="M214.6 156.1h1.5M214.6 155.9h1M214.6 155.7h.6M214.6 155.4h.1M214.6 140.1l2.5 1.3-2.5 1.3zM214.6 145.2l2.5 1.3-2.5 1.3zM214.6 155.4l2.5 1.3-2.5 1.2zM214.6 147.7h.2M214.6 147.4h.6M214.6 147.2h1.1M214.6 147h1.5M214.6 146.8h2"/>
<path d="M214.6 146.6h2.4M214.6 146.3h2.2M214.6 146.1h1.8M214.6 145.9h1.3M214.6 145.7h.9M214.6 145.5h.5M214.6 145.2h.1M215.4 143.4l1.4 1.4M215.4 158.7l1.4 1.4M215.4 148.5l1.4 1.4M215.9 149.5l.5-.5 .4 .9zM215.9 144.5l.5-.5 .4 .8z"/>
<path d="M215.9 159.7l.5-.5 .4 .9zM215.9 144.4h.7M215.9 149.5h.7M216 159.7h.6M216 159.6h.6M216 149.6h.6M216 144.5h.6M216 144.3h.5M216 149.4h.5M216.1 159.5h.4M216.2 144.2h.3M216.2 149.2h.3"/>
<path d="M216.2 159.4h.3M216.2 159.9h.5M216.3 144.1h.1M216.3 149.7h.4M216.3 149.1h.1M216.3 144.7h.4M216.3 159.3h.1M216.5 160h.2M216.5 143.3l1.4 1.4M216.5 158.6l1.4 1.4M216.5 148.4l1.4 1.4M216.6 149.8h.1"/>
<path d="M216.6 144.8h.1M217 144.3l.5-.5 .4 .9zM217 159.6l.5-.5 .4 .9zM217 149.4l.5-.5 .4 .9zM217.1 144.3h.6M217.1 149.4h.6M217.1 159.6h.7M217.1 159.5h.6M217.1 140.6h.3M217.1 142.6h.3M217.1 142.3h.3M217.1 142.1h.3"/>
<path d="M217.1 141.9h.3M217.1 141.7h.3M217.1 141.2h.3M217.1 141h.3M217.1 140.8h.3M217.1 140.3h.3M217.1 140.1h.3v2.6h-.3zM217.1 155.4h.3v2.5h-.3zM217.1 157.7h.3M217.1 157.5h.3M217.1 157.2h.3M217.1 157h.3"/>
<path d="M217.1 156.8h.3M217.1 156.6h.3M217.1 156.3h.3M217.1 156.1h.3M217.1 155.9h.3M217.1 155.7h.3M217.1 155.4h.3M217.1 145.2v2.6M217.2 149.5h.6M217.2 144.2h.5M217.2 149.2h.5M217.2 144.4h.6"/>
<path d="M217.2 159.4h.5M217.3 144.1h.3M217.3 149.1h.3M217.3 159.3h.3M217.4 159.7h.4M217.4 143.9h.2M217.4 149h.2M217.5 159.1h.1M217.5 149.6h.3M217.5 144.5h.3M217.7 159.9h.2M217.7 149.7h.2"/>
<path d="M217.8 144.7h.1M227.3 141.4v5.1h5.1M227.3 156.7v5h5.1M232.4 140.5h5.1v1.8h-5.1zM232.4 145.6h5.1v1.8h-5.1zM232.4 155.8h5.1v1.7h-5.1zM237.5 141.4h17.7M237.5 156.7h10.1M242.5 141.4v5.1h-5M242.5 156.7v5h-5M254.2 140.4l2.1 2M256.3 140.4l-2.1 2"/>
<path d="M16.5 173.7h3.8M107.9 171.9v5.1h12.7v-5.1M113 160.5l2.5 1.2-2.5 1.3zM113 170.6l2.5 1.3-2.5 1.3zM113 175.7l2.5 1.3-2.5 1.2zM113 172.8h.8M113 171h.8M113 173h.3M113 172.6h1.2M113 172.3h1.7M113 172.1h2.1M113 171.7h2.1"/>
<path d="M113 171.4h1.7M113 171.2h1.2M113 170.8h.3M113 177.9h.7M113 162.8h.5M113 162.6h.9M113 162.3h1.3M113 162.1h1.8M113 161.9h2.2M113 161.7h2.4M113 161.5h2M113 161.2h1.6"/>
<path d="M113 161h1.1M113 160.8h.7M113 160.6h.2M113 178.1h.3M113 177.7h1.2M113 177.4h1.6M113 177.2h2M113 176.8h2.2M113 176.6h1.7M113 176.3h1.3M113 176.1h.9M113 175.9h.4"/>
<path d="M113.8 173.9l1.4 1.4M113.8 163.8l1.4 1.4M113.8 179l1.4 1.4M114.3 174.9l.9 .4M114.3 164.8l.5-.5 .4 .9zM114.3 174.9h.7M114.3 164.8h.7M114.4 164.7h.6M114.4 174.8h.6M114.4 179.9h.6M114.5 164.6h.4M114.5 174.7h.4"/>
<path d="M114.6 175h.5M114.6 179.8h.3M114.6 164.9h.5M114.6 164.4h.3M114.7 174.6h.2M114.7 179.6h.2M114.7 164.3h.1M114.8 174.5h.1M114.8 174.4l-.5 .5M114.8 174.4l.4 .9M114.8 179.5l-.5 .5M114.8 179.5l.4 .9"/>
<path d="M114.8 179.5h.1M114.9 175.2h.2M114.9 165h.2M114.9 173.8l1.4 1.4M114.9 163.6l1.4 1.4M114.9 178.9l1.4 1.4M115.1 175.3h.1M115.4 164.7l.5-.6 .4 .9zM115.4 179.9l.5-.5 .4 .9zM115.4 174.8h.8M115.4 179.9h.8M115.5 164.7h.7"/>
<path d="M115.5 164.6h.6M115.5 160.5v2.5M115.5 170.6h.3v2.6h-.3zM115.5 175.7v2.5M115.5 172.8h.3M115.5 171h.3M115.5 174.7h.6M115.5 173h.3M115.5 172.6h.3M115.5 172.3h.3M115.5 172.1h.3M115.5 171.7h.3"/>
<path d="M115.5 171.4h.3M115.5 171.2h.3M115.5 170.8h.3M115.6 179.8h.5M115.7 164.4h.4M115.7 174.6h.4M115.7 179.6h.4M115.7 174.9h.5M115.8 164.3h.2M115.8 174.5h.2M115.8 164.8h.4M115.8 179.5h.2"/>
<path d="M115.9 164.2h.1M115.9 174.3h.1M115.9 174.3l-.5 .5 .9 .4M115.9 174.3l.4 .9M115.9 179.4h.1M116 175h.3M116.1 164.9h.2M116.3 175.2h.1M125.7 171.9v5.1h5.1M130.8 160.8h5.1v1.8h-5.1zM130.8 171h5.1v1.8h-5.1zM130.8 176.1h5.1v1.8h-5.1z"/>
<path d="M135.9 171.9h10.1M140.9 171.9v5.1h-5M209.5 171.9v5.1h12.7v-5.1M212.1 179.5l.3 1M214.6 175.7l2.5 1.3-2.5 1.2zM214.6 172.8h.8M214.6 171h.8M214.6 173h.3M214.6 172.6h1.2M214.6 172.3h1.7M214.6 172.1h2.1M214.6 171.7h2.1"/>
<path d="M214.6 171.4h1.7M214.6 171.2h1.2M214.6 170.8h.3M214.6 177.9h.7M214.6 160.5l2.5 1.2-2.5 1.3zM214.6 170.6l2.5 1.3-2.5 1.3zM214.6 162.8h.5M214.6 162.6h.9M214.6 162.3h1.3M214.6 162.1h1.8M214.6 161.9h2.2M214.6 161.7h2.4"/>
<path d="M214.6 161.5h2M214.6 161.2h1.5M214.6 161h1.1M214.6 160.8h.6M214.6 160.6h.2M214.6 178.1h.3M214.6 177.7h1.2M214.6 177.4h1.6M214.6 177.2h2M214.6 176.8h2.2M214.6 176.6h1.7M214.6 176.3h1.3"/>
<path d="M214.6 176.1h.8M214.6 175.9h.4M215.4 173.9l1.4 1.4M215.4 163.8l1.4 1.4M215.4 179l1.4 1.4M215.9 174.9h.7M215.9 174.9l.9 .4M215.9 164.8l.5-.5 .4 .9zM215.9 164.8h.7M216 164.7h.6M216 174.8h.6M216 179.9h.5"/>
<path d="M216.1 164.6h.4M216.1 174.7h.4M216.1 179.8h.4M216.2 175h.5M216.2 164.9h.5M216.2 164.4h.3M216.2 174.6h.3M216.3 179.6h.2M216.3 164.3h.1M216.4 174.5h.1M216.4 179.5h.1M216.4 174.4l-.5 .5"/>
<path d="M216.4 174.4l.4 .9M216.4 179.5l-.5 .5M216.4 179.5l.4 .9M216.4 175.2h.3M216.5 165h.2M216.5 173.8l1.4 1.4M216.5 163.6l1.4 1.4M216.5 178.9l1.4 1.4M216.7 175.3h.1M217 174.8h.7M217 174.8l.9 .4M217 179.9h.7"/>
<path d="M217 164.7l.5-.6 .4 .9zM217 179.9l.9 .4M217 179.9l.5-.5 .4 .9M217.1 164.7h.7M217.1 164.6h.6M217.1 174.7h.6M217.1 172.8h.3M217.1 171h.3M217.1 173h.3M217.1 172.6h.3M217.1 172.3h.3M217.1 172.1h.3"/>
<path d="M217.1 171.7h.3M217.1 171.4h.3M217.1 171.2h.3M217.1 170.8h.3M217.1 170.6h.3v2.6h-.3zM217.1 160.5v2.5M217.1 175.7v2.5M217.1 179.8h.6M217.2 164.4h.5M217.3 174.6h.3M217.3 179.6h.3M217.3 174.9h.5"/>
<path d="M217.4 164.8h.4M217.4 164.3h.2M217.4 174.5h.2M217.4 179.5h.2M217.5 164.2h.1M217.5 174.3h.1M217.5 179.4h.1M217.5 174.3l-.5 .5M217.5 174.3l.4 .9M217.6 175h.2M217.7 164.9h.2M217.9 175.2h.1"/>
<path d="M227.3 171.9v5.1h5.1M232.4 160.8h5.1v1.8h-5.1zM232.4 171h5.1v1.8h-5.1zM232.4 176.1h5.1v1.8h-5.1zM237.5 171.9h10.1M242.5 171.9v5.1h-5M400 173.7h3.8M114.3 180l.9 .4M114.3 180h.7M114.5 180.1h.6M114.8 180.2h.3M115.1 180.4h.1"/>
<path d="M115.7 180h.5M116 180.1h.2M116.2 180.2h.1M212.8 181.4l.4 1M213.5 183.4l.4 1M214.2 185.3l.4 1M215 187.2l.3 1M215.7 189.2l.4 1M215.9 180l.9 .4M215.9 180h.7M216.1 180.1h.5M216.4 191.1l.4 1"/>
<path d="M216.4 180.2h.3M216.7 180.4h.1M217.1 193l.4 1M217.3 180h.5M217.6 180.1h.2M217.8 180.2h.1M217.9 195l.3 1M218.6 196.9l.4 1M219.3 198.8l.4 1M230.2 198.8l-.4 1M230.9 196.7l-.4 1.1M231.5 194.7l-.3 1.1"/>
<path d="M232.2 192.7l-.3 1.1M232.9 190.7l-.4 1M233.6 188.6l-.4 1.1M234.3 186.6l-.4 1.1M234.9 184.6l-.3 1.1M85.1 202.4h45.7M85.1 207.5h15.2v25.3h30.5M85.1 204.9h17.8v12.7h27.9M85.1 210h12.7v38.1h33M107.9 202.4v5.1h12.7v-5.1M107.9 217.6v5.1h12.7v-5.1M113 201.1l2.5 1.3-2.5 1.2z"/>
<path d="M113 206.2l2.5 1.3-2.5 1.2zM113 216.3l2.5 1.3-2.5 1.3zM113 201.4h.7M113 203.5h.4M113 203.2h.8M113 203h1.3M113 202.8h1.7M113 202.6h2.2M113 202.3h2.8M113 202.1h2.1M113 201.9h1.6M113 201.7h1.2"/>
<path d="M113 201.2h.3M113 208.3h.8M113 206.6h.8M113 218.8h.2M113 218.6h.6M113 218.3h1.1M113 218.1h1.5M113 217.9h2M113 217.7h2.4M113 217.4h2.3M113 217.2h1.8M113 217h1.4"/>
<path d="M113 216.8h.9M113 216.6h.5M113 216.3h.1M113 208.6h.3M113 208.1h1.2M113 207.9h1.7M113 207.7h2.1M113 207.2h2.1M113 207h1.7M113 206.8h1.2M113 206.3h.3M113.8 204.4l1.4 1.4"/>
<path d="M113.8 219.6l1.4 1.4M113.8 209.5l1.4 1.4M114.3 210.5h.7M114.4 205.3h.6M114.4 205.4h.6M114.4 210.4h.6M114.5 205.2h.4M114.5 210.3h.4M114.6 205.1h.3M114.6 210.2h.3M114.6 210.7h.5M114.7 205.6h.4"/>
<path d="M114.7 205h.1M114.7 210h.1M114.8 204.9l.4 .9-.9-.4zM114.8 210l.4 .9-.9-.4zM114.9 204.3l1.4 1.4M114.9 219.5l1.4 1.4M114.9 209.4l1.4 1.4M114.9 210.8h.2M114.9 205.7h.2M115.4 205.3l.5-.5 .4 .9zM115.5 205.2h.6M115.5 210.4h.7"/>
<path d="M115.5 210.3h.6M115.5 201.1h.3v2.5h-.3zM115.5 206.2v2.5M115.5 216.3h.3v2.6h-.3zM115.5 201.4h.3M115.5 205.3h.7M115.5 203.5h.3M115.5 203.2h.3M115.5 203h.3M115.5 202.8h.3M115.5 202.6h.3M115.5 202.1h.3"/>
<path d="M115.5 201.9h.3M115.5 201.7h.3M115.5 201.2h.3M115.5 218.8h.3M115.5 218.6h.3M115.5 218.3h.3M115.5 218.1h.3M115.5 217.9h.3M115.5 217.7h.3M115.5 217.4h.3M115.5 217.2h.3M115.5 217h.3"/>
<path d="M115.5 216.8h.3M115.5 216.6h.3M115.6 205.1h.5M115.6 210.2h.5M115.7 205h.3M115.8 210h.2M115.8 210.5h.4M115.8 205.4h.4M115.9 204.9h.1M115.9 209.9h.1M115.9 209.9l-.5 .5 .9 .4M115.9 209.9l.4 .9"/>
<path d="M116.1 210.7h.2M116.1 205.6h.2M125.7 202.4v5.1h5.1M125.7 217.6v5.1h5.1M130.8 201.5h5.1v1.8h-5.1zM130.8 206.6h5.1v1.7h-5.1zM130.8 216.7h5.1v1.8h-5.1zM135.9 202.4h17.7M135.9 217.6h17.7M140.9 202.4v5.1h-5M140.9 217.6v5.1h-5M146 202.4v55.8h-50.8v-45.7h-10.1"/>
<path d="M152.6 201.4l2.1 2M152.6 216.6l2.1 2M154.7 201.4l-2.1 2M154.7 216.6l-2.1 2M16.5 224.2h3.8M107.9 232.8v5.1h12.7v-5.1M113 221.4l2.5 1.3-2.5 1.2zM113 231.6l2.5 1.2-2.5 1.3zM113 236.6l2.5 1.3-2.5 1.3zM113 233.9h.5M113 233.7h.9M113 233.4h1.3"/>
<path d="M113 233.2h1.8M113 233h2.2M113 232.8h2.4M113 232.6h2M113 232.3h1.6M113 232.1h1.1M113 231.9h.7M113 231.7h.2M113 238.8h.8M113 223.9h.1M113 223.7h.6M113 223.4h1"/>
<path d="M113 223.2h1.5M113 223h1.9M113 222.8h2.4M113 222.6h2.3M113 222.3h1.9M113 222.1h1.4M113 221.9h1M113 221.7h.5M113 221.4h.1M113 239h.4M113 238.5h1.3M113 238.3h1.7"/>
<path d="M113 238.1h2.2M113 237.7h2.1M113 237.4h1.6M113 237.2h1.2M113 237h.7M113 236.8h.3M113.8 234.9l1.4 1.4M113.8 224.7l1.4 1.4M113.8 239.9l1.4 1.4M114.3 220.6l.5-.5 .4 .9zM114.3 235.9l.5-.5 .4 .9zM114.3 225.7l.9 .4"/>
<path d="M114.3 225.7l.5-.5 .4 .9M114.3 220.7h.7M114.3 225.7h.7M114.3 235.9h.7M114.4 220.5h.6M114.4 225.6h.6M114.4 235.7h.6M114.5 236h.5M114.5 220.4h.4M114.5 225.5h.4M114.6 225.8h.5M114.6 220.8h.5"/>
<path d="M114.6 235.6h.3M114.6 220.3h.3M114.7 225.4h.2M114.7 235.5h.2M114.8 220.2h.1M114.8 236.1h.3M114.8 225.2h.1M114.8 226h.3M114.9 220.9h.2M114.9 234.7l1.4 1.4M114.9 224.6l1.4 1.4M114.9 239.8l1.4 1.4"/>
<path d="M115 236.2h.1M115.1 226.1h.1M115.1 221h.1M115.4 220.5l.5-.5 .4 .9zM115.4 235.8l.5-.6 .4 .9zM115.4 225.6l.5-.5 .4 .9zM115.4 220.5h.8M115.4 225.6h.8M115.5 235.7h.6M115.5 221.4v2.5M115.5 231.6h.3v2.5h-.3zM115.5 236.6v2.6"/>
<path d="M115.5 220.4h.6M115.5 233.9h.3M115.5 233.7h.3M115.5 233.4h.3M115.5 233.2h.3M115.5 233h.3M115.5 232.8h.3M115.5 232.6h.3M115.5 232.3h.3M115.5 232.1h.3M115.5 231.9h.3M115.5 231.7h.3"/>
<path d="M115.5 225.5h.6M115.6 235.6h.5M115.6 235.9h.6M115.7 220.3h.4M115.7 225.4h.4M115.7 235.5h.3M115.7 225.7h.5M115.7 220.7h.5M115.8 220.2h.2M115.8 225.2h.2M115.8 235.4h.2M115.9 220h.1"/>
<path d="M115.9 225.1h.1M115.9 236h.3M116 225.8h.3M116 220.8h.3M116.2 236.1h.1M116.3 226h.1M116.3 220.9h.1M125.7 232.8v5.1h5.1M130.8 221.8h5.1v1.8h-5.1zM130.8 231.9h5.1v1.8h-5.1zM130.8 237h5.1v1.8h-5.1zM135.9 232.8h10.1"/>
<path d="M140.9 232.8v5.1h-5M400 224.2h3.8M107.9 248.1v5.1h12.7v-5.1M113 246.8l2.5 1.3-2.5 1.2zM113 251.9l2.5 1.3-2.5 1.2zM113 247.2h.8M113 249.2h.3M113 249h.7M113 248.8h1.2M113 248.6h1.6M113 248.3h2M113 247.9h2.2"/>
<path d="M113 247.7h1.7M113 247.4h1.3M113 247h.4M113 254.3h.2M113 254.1h.6M113 253.9h1.1M113 253.7h1.5M113 253.4h2M113 253.2h2.4M113 253h2.2M113 252.8h1.8M113 252.6h1.3"/>
<path d="M113 252.3h.9M113 252.1h.5M113 251.9h.1M113.8 250.1l1.4 1.4M113.8 255.2l1.4 1.4M114.3 251.1l.5-.5 .4 .9zM114.3 241l.5-.5 .4 .8zM114.3 256.2l.5-.5 .4 .9zM114.3 240.9h.7M114.4 251.1h.6M114.4 256.2h.6M114.4 251.2h.6"/>
<path d="M114.4 256.1h.6M114.4 241h.6M114.5 240.8h.4M114.5 250.9h.4M114.5 256h.4M114.6 240.7h.3M114.6 250.8h.3M114.6 255.9h.3M114.6 256.3h.5M114.7 251.3h.4M114.7 240.6h.1M114.7 250.7h.1"/>
<path d="M114.7 241.2h.4M114.7 255.8h.1M114.9 250l1.4 1.4M114.9 255.1l1.4 1.4M114.9 256.5h.2M115 251.4h.1M115 241.3h.1M115.4 256.1l.5-.5 .4 .9zM115.5 240.8h.6M115.5 250.9h.6M115.5 256h.6M115.5 256.1h.7"/>
<path d="M115.5 246.8h.3v2.5h-.3zM115.5 251.9v2.5M115.5 247.2h.3M115.5 251.1h.7M115.5 249.2h.3M115.5 249h.3M115.5 248.8h.3M115.5 248.6h.3M115.5 248.3h.3M115.5 247.9h.3M115.5 247.7h.3M115.5 247.4h.3"/>
<path d="M115.5 247h.3M115.6 240.7h.5M115.6 250.8h.5M115.6 240.9h.6M115.6 255.9h.5M115.7 240.6h.3M115.7 250.7h.3M115.8 255.8h.2M115.8 256.2h.4M115.8 251.2h.4M115.8 240.4h.2M115.9 250.6h.1"/>
<path d="M115.9 255.6h.1M115.9 241h.3M115.9 250.5l.4 .9-.9-.4zM115.9 240.3l.4 .9-.9-.4zM116.1 256.3h.2M116.1 251.3h.2M116.2 241.2h.1M125.7 248.1v5.1h5.1M130.8 247.2h5.1v1.8h-5.1zM130.8 252.3h5.1v1.7h-5.1zM135.9 248.1h10.1M140.9 248.1v5.1h-5"/>
<path d="M226.8 253.2h1M227.3 252.6v1.1M239.5 253.2h1M240 252.6v1.1M313.6 249.3h86.4M313.6 254.4h86.4M313.6 259.5h86.4M372.1 259.5v5.1M67.8 274.7v3.9M115.2 274.7v3.9M162.7 274.7v3.9M210.2 274.7v3.9"/>
<path d="M226.8 260.8h1M227.3 260.3v1M239.5 260.8h1M240 260.3v1M253.9 263.3h.4M253.9 263.2h.4M253.9 263.1h.4M253.9 263h.4M253.9 262.9h.4M253.9 262.8h.4M253.9 262.7h.4M253.9 262.6h.4"/>
<path d="M254 263.5h.4M254 263.4h.4M254 262.4h.4M254 263.5l.5 .1M254 263.6h1.3M254 262.3h1.3M254 263.7h1.3M254.1 262.2h1.2M254.1 263.7h1.2M254.1 262.1h1.1M254.2 263.9h.9M254.3 262h.8"/>
<path d="M254.3 263.9h.7M254.3 262h.7M254.3 262.6h-.4M254.4 262.5h-.4M254.5 264h.4M254.5 262.4h-.5M254.5 261.9h.3M254.6 262.3h-.6M254.8 262.3h.6M254.9 262.4h.5M255 262.4h.4M255 263.4h.4"/>
<path d="M255 262.5h.4M255 263.3h.4M255 263.2h.4M255 263.1h.4M255 263h.4M255 262.9h.4M255 262.8h.4M255 262.7h.4M255 262.6h.4M255.2 263.8h-1.1M255.4 263.5l-.6 .1M255.4 263.5h-.5"/>
<path d="M255.9 264.5h.3M255.9 264.4h.3M255.9 264.3h.3M255.9 264.2h.3M255.9 264.1h.3M255.9 264h.4M255.9 263.6h1.4M255.9 263.5l.5 .1M255.9 263.5h.4M255.9 263.4l.4 .1M255.9 263.4h.3M255.9 263.3h.3"/>
<path d="M255.9 263.2h.3M255.9 263.1h.3M255.9 263h.3M255.9 262.9h.3M255.9 262.8h.3M255.9 262.7h.3M255.9 262.6h.3M256 262.2h1.2M256 262.1h1.2M256.1 264.7h-.2M256.1 262.1h1M256.2 262h.8"/>
<path d="M256.2 264.6h-.3M256.2 264.5l-.3 .1M256.2 262h.7M256.3 262.5h-.4M256.3 262.4l-.4 .1M256.4 264h.4M256.4 262.4h-.5M256.4 261.9h.3M256.5 262.3h-.6M256.7 262.3h.6M256.7 263.6h.6M256.8 262.4h.5"/>
<path d="M256.9 262.4h.4M256.9 262.5h.4M256.9 263.4h.4M256.9 263.3h.4M256.9 262.6h.4M256.9 263.2h.4M256.9 263.1h.4M256.9 263h.4M256.9 262.9h.4M256.9 262.8h.4M256.9 262.7h.4M257 263.9l-1.1 .1"/>
<path d="M257.1 263.9h-1.2M257.1 263.8h-1.2M257.2 263.7l-1.3 .1M257.2 263.7h-1.3M257.2 262.3h-1.3M257.3 263.5h-.5M257.3 263.4h-.4M257.6 274.7v3.9M257.8 263.4l.4 .1M257.8 263.4h.4M257.8 262.8h1.4M257.8 262.7l.3 .1"/>
<path d="M257.8 262.7h.3M257.8 262.5h.4M257.8 263.5h.5M257.8 263.5l.6 .1M257.8 263.6h1.3M257.9 263.7h1.2M257.9 262.2h1.2M257.9 262.1h1.2M258 263.8h1M258 262.1h1M258 263.9h1M258.1 262h.8"/>
<path d="M258.1 263.9h.8M258.1 262.6l-.3 .1M258.1 262h.7M258.2 262.6h-.4M258.2 263.3h-.4M258.2 262.4l-.4 .1M258.3 262.4h-.5M258.3 264h.4M258.3 263.2l-.5 .1M258.4 262.8h.8M258.4 261.9h.2M258.4 262.3h-.6"/>
<path d="M258.5 263.2h-.7M258.5 262.7h.7M258.6 262.3h.6M258.6 263.1h-.8M258.6 262.7h.6M258.7 262.4h.5M258.7 263.5h.5M258.8 263l-1 .1M258.8 262.4h.4M258.8 263.5h.4M258.8 262.6h.4M258.8 262.5h.4"/>
<path d="M258.8 263.4h.4M258.8 263.3h.4M258.8 263.2h.4M258.9 263h-1.1M258.9 263.2h.3M259 263.1h.2M259 262.9l-1.2 .1M259.1 262.9h-1.3M259.1 262.2l-1.2 .1M259.2 263.5l-.5 .1M259.7 263.8h.4M259.7 263.7h.4"/>
<path d="M259.7 263.6h.4M259.7 263.5h.4M259.7 263.4h.4M259.7 263.3h.4M259.7 263.2h.4M259.7 263.1h.4M259.7 263h.4M259.7 262.9h.4M259.7 262.8h.4M259.7 262.7h.4M259.7 262.6h.4M259.7 264h.1"/>
<path d="M259.8 262.3h1.3M259.8 262.2h1.2M259.8 262.1h1.2M259.9 262.1h1M260 263.9h-.3M260 262h.8M260.1 263.9h-.4M260.1 262h.7M260.1 262.5h-.4M260.1 262.4l-.4 .1M260.2 262.4h-.5M260.2 261.9h.4"/>
<path d="M260.3 262.3h-.6M260.5 262.3h.6M260.6 262.4h.5M260.7 262.4h.4M260.7 262.5h.4M260.8 263.8h.4M260.8 263.7h.4M260.8 263.6h.4M260.8 263.5h.4M260.8 263.4h.4M260.8 263.3h.4M260.8 263.2h.4"/>
<path d="M260.8 263.1h.4M260.8 263h.4M260.8 262.9h.4M260.8 262.8h.4M260.8 262.7h.4M260.8 262.6h.4M260.8 264h.1M261 263.9h-.2M261.1 263.9h-.3M262.8 264h.2M262.8 261.5h.3M262.8 263.9h.3"/>
<path d="M262.8 263.8h.3M262.8 263.7h.3M262.8 263.6h.3M262.8 263.5h.3M262.8 263.4h.3M262.8 263.3h.3M262.8 263.2h.3M262.8 263.1h.3M262.8 263h.3M262.8 262.9h.3M262.8 262.8h.3M262.8 262.7h.3"/>
<path d="M262.8 262.6h.3M262.8 262.3h1.3M262.8 262.2l1.2 .1M262.8 262.2h1.2M262.8 262.1h1.1M262.8 262l.3 .1M262.8 262h.3M262.8 261.9h.3M262.8 261.8h.3M262.8 261.7h.3M262.8 261.6h.3M262.8 261.4h.3"/>
<path d="M263 261.3h.1M263.1 263.9l-.3 .1M263.2 262.5h-.4M263.2 262.4l-.4 .1M263.2 262.1h.6M263.3 262.4h-.5M263.4 262h.1M263.7 262.4h.4M263.8 262.5h.3M263.8 262.6h.4M263.9 262.7h.3M263.9 262.6h.3"/>
<path d="M263.9 264h.1M263.9 263.9h.2M263.9 263.8h.3M263.9 263.7h.3M263.9 263.6h.3M263.9 263.5h.3M263.9 263.4h.3M263.9 263.3h.3M263.9 263.2h.3M263.9 263.1h.3M263.9 263h.3M263.9 262.9h.3"/>
<path d="M263.9 262.8h.3M264.1 263.9l-.2 .1M264.6 263.5l.3 .1M264.6 263.5h.3M264.6 262.7h.3M264.6 263.7h.4M264.6 263.6h.4M264.6 263.7l.9 .1M264.7 263.8h.8M264.7 263.9h.8M264.7 262.8h-.1M264.8 262.3h1"/>
<path d="M264.8 263.9h.7M264.8 262.2h1M264.9 262.7l-.3 .1M264.9 262.1h.8M264.9 262.6l-.3 .1M264.9 264h.6M264.9 263.4l-.3 .1M264.9 262.6h-.3M265 262.5h-.4M265 263.4h-.4M265 263h1M265 262.1h.6"/>
<path d="M265 262.4l-.4 .1M265.1 263.3h-.5M265.1 262.4h-.4M265.1 263h.9M265.2 264l-.1 .1M265.2 263.2l-.6 .1M265.2 264.1h.1M265.2 262h.2M265.3 262.9h.7M265.4 263.2h-.7M265.4 262.8h.6M265.5 262.4h.4"/>
<path d="M265.5 262.8h.5M265.6 263.1h-.8M265.6 262.4l.3 .1M265.6 262.5h.4M265.6 263.1h.4M265.6 262.7h.4M265.6 262.6h.4M265.7 262.6h.3M265.7 263.9h.3M265.7 263.8h.3M265.7 263.7h.3M265.7 263.6h.3"/>
<path d="M265.7 263.5h.3M265.7 263.4h.3M265.7 263.3h.3M265.7 263.2h.3M265.8 264h-.1M265.9 262.3h-1.2M266 263.9l-.3 .1M266 263.1h-1.2M266.4 263.8h.3M266.4 263.7h.3M266.4 263.6h.3M266.4 263.5h.3"/>
<path d="M266.4 263.4h.3M266.4 263.3h.3M266.4 263.2h.3M266.4 263.1h.3M266.4 263h.3M266.4 262.9h.3M266.4 262.8h.3M266.4 262.7h.3M266.4 262.6h.3M266.6 264h-.2M266.6 262.3h1M266.6 262.2h1"/>
<path d="M266.7 263.9l-.3 .1M266.7 262.1h.8M266.7 263.9h-.3M266.7 262.6h-.3M266.8 262.5h-.4M266.8 262.1h.6M266.8 262.4l-.3 .1M266.9 262.4h-.4M267 262h.1M267.3 262.4h.4M267.4 262.4l.4 .1M267.4 262.5h.4"/>
<path d="M267.4 262.6h.4M267.5 262.6h.3M267.7 262.3h-1.2M267.7 262.7l-.2 .1M267.8 262.7h-.3M268.2 263.4h.3M268.2 263.3h.3M268.2 263.2h.3M268.2 263.1h.3M268.2 263h.3M268.2 262.9h.3M268.2 262.8h.3"/>
<path d="M268.2 262.7h.3M268.2 262.6h.3M268.2 263.5h.3M268.3 263.6l.3 .1M268.3 263.5l.3 .1M268.3 263.7h.4M268.3 263.7h1.2M268.4 263.8h1.1M268.4 262.3h1.2M268.4 263.9h1M268.4 262.2h1.2M268.5 263.9h.8"/>
<path d="M268.5 262.1h1.1M268.6 262.6h-.4M268.6 262.5h-.3M268.6 264h.6M268.6 262.1h.6M268.6 262.4l-.3 .1M268.7 262.4h-.4M268.8 264v.1M268.8 262h.2M268.9 264v.1M268.9 264.1h.1M269.1 262.4h.5"/>
<path d="M269.2 263.7h.3M269.2 262.4h.4M269.2 262.5h.4M269.3 263.4h.3M269.3 263.3h.3M269.3 263.2h.3M269.3 263.1h.3M269.3 263h.3M269.3 262.9h.3M269.3 262.8h.3M269.3 262.7h.3M269.3 262.6h.3"/>
<path d="M269.3 262h.3M269.3 261.9h.3M269.3 261.8h.3M269.3 261.7h.3M269.3 261.6h.3M269.3 261.5h.3M269.4 261.4h.2M269.5 261.3h.1M269.5 263.7h-.4M269.6 263.5l-.4 .1M269.6 263.5h-.3M269.6 262.3h-1.3"/>
<path d="M269.9 263.5h.3M269.9 263.4h.3M269.9 263.3h.3M269.9 263.2h.3M269.9 263.1h.3M269.9 263h.3M269.9 262.9h.3M269.9 262.8h.3M269.9 262.7h.3M269.9 262.6h.3M269.9 262.5h.3M269.9 262.4h.3"/>
<path d="M269.9 262.3h.3M269.9 262.2h.3M269.9 263.7h1.6M269.9 263.7h.3M269.9 263.6h.3M269.9 263.5l.3 .1M269.9 262.1h.3M269.9 263.8h1.6M270 263.9h1.4M270 262.1h.2M270.1 264h.5M270.3 264.1h.1"/>
<path d="M270.4 264v.1M270.5 263.7h.5M270.6 263.6l.3 .1M270.6 263.5l.3 .1M270.6 263.5h.3M270.6 263.4h.3M270.6 263.3h.3M270.6 263.2h.3M270.6 263.1h.3M270.6 263h.3M270.6 262.9h.3M270.6 262.8h.3"/>
<path d="M270.6 262.7h.3M270.6 262.6h.3M270.6 262.5h.3M270.6 262.4h.3M270.6 262.3h.3M270.6 262.2h.3M270.6 262.1h.3M270.7 262.1h.2M270.8 264h.5M271.1 264.1h.1M271.2 263.7h.4M271.3 263.6h.3"/>
<path d="M271.3 263.5h.3M271.3 263.4h.3M271.3 263.3h.3M271.3 263.2h.3M271.3 263.1h.3M271.3 263h.3M271.3 262.9h.3M271.3 262.8h.3M271.3 262.7h.3M271.3 262.6h.3M271.3 262.5h.3M271.3 262.4h.3"/>
<path d="M271.3 262.3h.3M271.3 262.2h.3M271.3 262.1h.3M271.4 262.1h.2M271.5 263.9h-1.5M271.6 263.7h-.4M271.8 263.6h.4M271.8 263.5h.4M271.8 263.4h.4M271.9 263.7h.4M271.9 262.6h.3M271.9 263.7l.8 .1"/>
<path d="M271.9 263.8h.8M272 262.3h1.1M272 263.9h.8M272 262.8h-.1M272.1 263.9h.7M272.1 262.2h.9M272.1 262.7l-.2 .1M272.1 262.7h-.2M272.1 262.1h.8M272.2 262.6h-.3M272.2 264h.6M272.2 262.5h-.3"/>
<path d="M272.2 263.4h-.4M272.2 263h1M272.2 262.1h.6M272.3 262.4l-.4 .1M272.3 263.3h-.4M272.4 262.4h-.5M272.4 264.1h.1M272.4 263h.8M272.5 263.2l-.6 .1M272.5 262h.1M272.5 262.9h.7M272.6 263.2h-.7"/>
<path d="M272.6 262.8h.6M272.7 262.4h.5M272.8 262.8h.4M272.8 262.4h.4M272.8 263.1h-.8M272.9 262.5h.3M272.9 262.7h.3M272.9 262.6h.3M272.9 263.1h.3M272.9 263.9h.3M272.9 263.8h.3M272.9 263.7h.3"/>
<path d="M272.9 263.6h.3M272.9 263.5h.3M272.9 263.4h.3M272.9 263.3h.3M272.9 263.2h.3M273.1 264h-.2M273.2 263.9l-.3 .1M273.2 263l-1.1 .1M273.7 264h.1M273.7 263.9h.2M273.7 263.8h.2M273.7 263.7h.2"/>
<path d="M273.7 263.6h.2M273.7 263.5h.2M273.7 263.4h.2M273.7 263.3h.2M273.7 263.2h.2M273.7 263.1h.2M273.7 263h.2M273.7 262.9h.2M273.7 262.8h.2M273.7 262.7h.2M273.8 262.3h1.1M273.9 262.2h.9"/>
<path d="M273.9 263.9l-.2 .1M273.9 262.1h.9M274 262.6l-.3 .1M274 262.6h-.3M274 262.5h-.3M274 262.1h.6M274.1 262.4l-.4 .1M274.2 262.4h-.5M274.3 262h.1M274.5 262.4h.5M274.6 262.4l.4 .1M274.7 262.5h.3"/>
<path d="M274.7 262.6h.3M274.9 262.3h-1.1M275 262.7l-.3 .1M275 262.7h-.3M275.5 263.5l.3 .1M275.5 263.5h.3M275.5 263.4h.3M275.5 263h1.1M275.5 262.9l.3 .1M275.5 262.9h.3M275.5 262.8h.3M275.5 262.7h.3"/>
<path d="M275.5 262.6h.3M275.5 263.6h.4M275.5 263.7h.5M275.6 263.7h1.1M275.6 262.3h1.2M275.6 262.3h1.1M275.7 263.9h.9M275.7 262.2h.9M275.7 262.1h.9M275.8 263.4h-.3M275.8 262.5h-.3M275.9 264h.6"/>
<path d="M275.9 262.1h.5M275.9 262.4l-.4 .1M275.9 263.3h-.4M276 262.4h-.5M276 264.1h.1M276.1 263.2l-.6 .1M276.1 262h.1M276.1 264l.1 .1M276.2 263.2h-.7M276.2 262.8h.6M276.3 262.8h.5M276.3 262.4h.5"/>
<path d="M276.4 263.1h-.9M276.4 262.4h.4M276.5 262.7h.3M276.5 262.5h.3M276.5 263.5h.3M276.5 263l-1 .1M276.5 262.6h.3M276.6 263.4h.2M276.6 263.3h.2M276.7 263.8h-1.1M276.7 263.3h.1M276.8 263.7h-.4"/>
<path d="M276.8 262.9l-.9 .1M276.8 263.6h-.4M276.8 262.9h-.7M276.8 263.5h-.3M305.1 274.7v3.9M313.6 264.6h86.4M313.6 269.7h86.4M352.6 274.7v3.9M400 274.6h.1"/>
<circle cx="227.3" cy="253.2" r="2.03"/>
<circle cx="227.3" cy="253.2" r=".51"/>
<circle cx="240" cy="253.2" r="2.03"/>
<circle cx="240" cy="253.2" r=".51"/>
<circle cx="227.3" cy="260.8" r="2.03"/>
<circle cx="227.3" cy="260.8" r=".51"/>
<circle cx="240" cy="260.8" r="2.03"/>
<circle cx="240" cy="260.8" r=".51"/>
</g>
<g fill="none" stroke="#000" stroke-width=".61">
<path d="M20.3 22.1h379.7v252.6h-379.7zM83.8 55.1h1.3M83.8 52.5h1.3M83.8 50h1.3M83.8 57.6h1.3M185.4 55.1h1.3M185.4 52.5h1.3M185.4 50h1.3M185.4 57.6h1.3M83.8 60.2h1.3M185.4 60.2h1.3M284.4 90.6h61v61h-61z"/>
<path d="M314.9 90.6v61M83.8 131.3h1.3M83.8 128.7h1.3M83.8 126.2h1.3M83.8 136.3h1.3M83.8 133.8h1.3M185.4 131.3h1.3M185.4 128.7h1.3M185.4 126.2h1.3M185.4 136.3h1.3M185.4 133.8h1.3M83.8 207.5h1.3"/>
<path d="M83.8 204.9h1.3M83.8 202.4h1.3M83.8 212.5h1.3M83.8 210h1.3M313.6 244.3v30.4M400 244.3h-116.8v30.4"/>
</g>
<g fill="none" stroke="#000" stroke-width="2.5">
<circle cx="288.2" cy="95.7" r="1.27"/>
<circle cx="295.9" cy="95.7" r="1.27"/>
<circle cx="303.5" cy="95.7" r="1.27"/>
<circle cx="311.1" cy="95.7" r="1.27"/>
<circle cx="318.7" cy="95.7" r="1.27"/>
<circle cx="326.3" cy="95.7" r="1.27"/>
<circle cx="334" cy="95.7" r="1.27"/>
<circle cx="341.6" cy="95.7" r="1.27"/>
<circle cx="288.2" cy="108.4" r="1.27"/>
<circle cx="295.9" cy="108.4" r="1.27"/>
<circle cx="303.5" cy="108.4" r="1.27"/>
<circle cx="311.1" cy="108.4" r="1.27"/>
<circle cx="318.7" cy="108.4" r="1.27"/>
<circle cx="326.3" cy="108.4" r="1.27"/>
<circle cx="334" cy="108.4" r="1.27"/>
<circle cx="341.6" cy="108.4" r="1.27"/>
<circle cx="288.2" cy="121.1" r="1.27"/>
<circle cx="288.2" cy="133.8" r="1.27"/>
<circle cx="295.9" cy="133.8" r="1.27"/>
<circle cx="295.9" cy="121.1" r="1.27"/>
<circle cx="303.5" cy="121.1" r="1.27"/>
<circle cx="303.5" cy="133.8" r="1.27"/>
<circle cx="311.1" cy="133.8" r="1.27"/>
<circle cx="311.1" cy="121.1" r="1.27"/>
<circle cx="318.7" cy="121.1" r="1.27"/>
<circle cx="318.7" cy="133.8" r="1.27"/>
<circle cx="326.3" cy="121.1" r="1.27"/>
<circle cx="326.3" cy="133.8" r="1.27"/>
<circle cx="334" cy="121.1" r="1.27"/>
<circle cx="334" cy="133.8" r="1.27"/>
<circle cx="341.6" cy="121.1" r="1.27"/>
<circle cx="341.6" cy="133.8" r="1.27"/>
<circle cx="288.2" cy="146.5" r="1.27"/>
<circle cx="295.9" cy="146.5" r="1.27"/>
<circle cx="303.5" cy="146.5" r="1.27"/>
<circle cx="311.1" cy="146.5" r="1.27"/>
<circle cx="318.7" cy="146.5" r="1.27"/>
<circle cx="326.3" cy="146.5" r="1.27"/>
<circle cx="334" cy="146.5" r="1.27"/>
<circle cx="341.6" cy="146.5" r="1.27"/>
</g>
<g fill="#000" stroke="#000" stroke-width=".25">
<path d="M225.3 253.2h1.5l.2 .4 .3 .1v1.5a2 2 0 0 1-2-2z" fill-rule="evenodd"/>
<path d="M227.3 251.1a2.04 2.04 0 0 1 2 2.1h-1.5l-.1-.3-.4-.3z" fill-rule="evenodd"/>
<path d="M238 253.2h1.5l.2 .4 .3 .1v1.5a2 2 0 0 1-2-2z" fill-rule="evenodd"/>
<path d="M240 251.1a2.04 2.04 0 0 1 2 2.1h-1.5l-.1-.3-.4-.3z" fill-rule="evenodd"/>
<path d="M225.3 260.8h1.5l.1 .3 .4 .2v1.5a2 2 0 0 1-2-2z" fill-rule="evenodd"/>
<path d="M227.3 258.7a2.04 2.04 0 0 1 2 2.1h-1.5l-.1-.3-.4-.2z" fill-rule="evenodd"/>
<path d="M238 260.8h1.5l.1 .3 .4 .2v1.5a2 2 0 0 1-2-2z" fill-rule="evenodd"/>
<path d="M240 258.7a2.04 2.04 0 0 1 2 2.1h-1.5l-.1-.3-.4-.2z" fill-rule="evenodd"/>
<circle cx="107.9" cy="50" r=".51"/>
<circle cx="120.6" cy="50" r=".51"/>
<circle cx="125.7" cy="50" r=".51"/>
<circle cx="140.9" cy="50" r=".51"/>
<circle cx="146" cy="50" r=".51"/>
<circle cx="209.5" cy="50" r=".51"/>
<circle cx="222.2" cy="50" r=".51"/>
<circle cx="227.3" cy="50" r=".51"/>
<circle cx="242.5" cy="50" r=".51"/>
<circle cx="247.6" cy="50" r=".51"/>
<circle cx="107.9" cy="65.2" r=".51"/>
<circle cx="120.6" cy="65.2" r=".51"/>
<circle cx="125.7" cy="65.2" r=".51"/>
<circle cx="140.9" cy="65.2" r=".51"/>
<circle cx="146" cy="65.2" r=".51"/>
<circle cx="209.5" cy="65.2" r=".51"/>
<circle cx="222.2" cy="65.2" r=".51"/>
<circle cx="227.3" cy="65.2" r=".51"/>
<circle cx="242.5" cy="65.2" r=".51"/>
<circle cx="247.6" cy="65.2" r=".51"/>
<circle cx="107.9" cy="95.7" r=".51"/>
<circle cx="107.9" cy="80.5" r=".51"/>
<circle cx="120.6" cy="80.5" r=".51"/>
<circle cx="120.6" cy="95.7" r=".51"/>
<circle cx="125.7" cy="80.5" r=".51"/>
<circle cx="125.7" cy="95.7" r=".51"/>
<circle cx="140.9" cy="80.5" r=".51"/>
<circle cx="140.9" cy="95.7" r=".51"/>
<circle cx="146" cy="80.5" r=".51"/>
<circle cx="146" cy="95.7" r=".51"/>
<circle cx="209.5" cy="95.7" r=".51"/>
<circle cx="209.5" cy="80.5" r=".51"/>
<circle cx="222.2" cy="80.5" r=".51"/>
<circle cx="222.2" cy="95.7" r=".51"/>
<circle cx="227.3" cy="95.7" r=".51"/>
<circle cx="227.3" cy="80.5" r=".51"/>
<circle cx="242.5" cy="95.7" r=".51"/>
<circle cx="242.5" cy="80.5" r=".51"/>
<circle cx="247.6" cy="80.5" r=".51"/>
<circle cx="247.6" cy="95.7" r=".51"/>
<circle cx="107.9" cy="126.2" r=".51"/>
<circle cx="120.6" cy="126.2" r=".51"/>
<circle cx="125.7" cy="126.2" r=".51"/>
<circle cx="140.9" cy="126.2" r=".51"/>
<circle cx="146" cy="126.2" r=".51"/>
<circle cx="209.5" cy="126.2" r=".51"/>
<circle cx="222.2" cy="126.2" r=".51"/>
<circle cx="227.3" cy="126.2" r=".51"/>
<circle cx="242.5" cy="126.2" r=".51"/>
<circle cx="247.6" cy="126.2" r=".51"/>
<circle cx="107.9" cy="156.7" r=".51"/>
<circle cx="107.9" cy="141.4" r=".51"/>
<circle cx="120.6" cy="141.4" r=".51"/>
<circle cx="120.6" cy="156.7" r=".51"/>
<circle cx="125.7" cy="156.7" r=".51"/>
<circle cx="125.7" cy="141.4" r=".51"/>
<circle cx="140.9" cy="156.7" r=".51"/>
<circle cx="140.9" cy="141.4" r=".51"/>
<circle cx="146" cy="156.7" r=".51"/>
<circle cx="146" cy="141.4" r=".51"/>
<circle cx="209.5" cy="156.7" r=".51"/>
<circle cx="209.5" cy="141.4" r=".51"/>
<circle cx="222.2" cy="156.7" r=".51"/>
<circle cx="222.2" cy="141.4" r=".51"/>
<circle cx="227.3" cy="141.4" r=".51"/>
<circle cx="227.3" cy="156.7" r=".51"/>
<circle cx="242.5" cy="141.4" r=".51"/>
<circle cx="242.5" cy="156.7" r=".51"/>
<circle cx="247.6" cy="141.4" r=".51"/>
<circle cx="247.6" cy="156.7" r=".51"/>
<circle cx="107.9" cy="171.9" r=".51"/>
<circle cx="120.6" cy="171.9" r=".51"/>
<circle cx="125.7" cy="171.9" r=".51"/>
<circle cx="140.9" cy="171.9" r=".51"/>
<circle cx="146" cy="171.9" r=".51"/>
<circle cx="209.5" cy="171.9" r=".51"/>
<circle cx="222.2" cy="171.9" r=".51"/>
<circle cx="227.3" cy="171.9" r=".51"/>
<circle cx="242.5" cy="171.9" r=".51"/>
<circle cx="247.6" cy="171.9" r=".51"/>
<circle cx="107.9" cy="217.6" r=".51"/>
<circle cx="107.9" cy="202.4" r=".51"/>
<circle cx="120.6" cy="217.6" r=".51"/>
<circle cx="120.6" cy="202.4" r=".51"/>
<circle cx="125.7" cy="217.6" r=".51"/>
<circle cx="125.7" cy="202.4" r=".51"/>
<circle cx="140.9" cy="217.6" r=".51"/>
<circle cx="140.9" cy="202.4" r=".51"/>
<circle cx="146" cy="217.6" r=".51"/>
<circle cx="146" cy="202.4" r=".51"/>
<circle cx="107.9" cy="232.8" r=".51"/>
<circle cx="120.6" cy="232.8" r=".51"/>
<circle cx="125.7" cy="232.8" r=".51"/>
<circle cx="140.9" cy="232.8" r=".51"/>
<circle cx="146" cy="232.8" r=".51"/>
<circle cx="107.9" cy="248.1" r=".51"/>
<circle cx="120.6" cy="248.1" r=".51"/>
<circle cx="125.7" cy="248.1" r=".51"/>
<circle cx="140.9" cy="248.1" r=".51"/>
<circle cx="146" cy="248.1" r=".51"/>
</g>
<g fill="#000" stroke="#000" stroke-width=".25">
<path d="M115.3 53.6h.5v3h-.5zM216.9 53.6h.5v3h-.5zM115.3 68.8h.5v3h-.5zM216.9 68.8h.5v3h-.5zM115.3 84h.5v3.1h-.5zM115.3 99.3h.5v3h-.5zM216.9 84h.5v3.1h-.5zM216.9 99.3h.5v3h-.5zM115.3 129.7h.5v3.1h-.5zM216.9 129.7h.5v3.1h-.5zM115.3 145h.5v3h-.5zM216.9 145h.5v3h-.5z"/>
<path d="M115.3 160.2h.5v3.1h-.5zM115.3 175.5h.5v3h-.5zM216.9 160.2h.5v3.1h-.5zM216.9 175.5h.5v3h-.5zM115.3 205.9h.5v3.1h-.5zM115.3 221.1h.5v3.1h-.5zM115.3 236.4h.5v3h-.5zM115.3 251.6h.5v3.1h-.5z"/>
</g>
<g fill="none" stroke="#000" stroke-width=".38">
<path d="M259.7 256.2h4M259.7 255.9h3.9M259.7 255.5h3.9M259.7 255.2h4M261 259.4h1.9M261 252.4h8.7M261.1 259h2.9M261.1 252h1.8M261.3 256.6h2.5M261.3 252.7h8.2M261.4 258.7h2.8M261.4 259.7h1.1"/>
<path d="M261.4 251.7h1.1M261.6 254.8l.5-1.2-1.2-1.4 1-1 1.4 1.2 1.2-.5 .2-1.9h1.4l.2 1.9 1.2 .5 1.4-1.2 1 1-1.2 1.4 .5 1.2M261.6 254.8l-1.9 .2v1.4l1.9 .2 .5 1.2-1.2 1.4 1 1 1.4-1.2 .6 .3 .8-2-.9-.7M261.6 254.8h2.3M261.6 253.1h7.6M261.6 258.3h2.7M261.7 256.9h2.4M261.7 254.5h2.4M261.8 251.3h.2M261.8 257.3h2.7M261.8 254.1h2.8M261.9 253.4h7"/>
<path d="M261.9 258h2.6M262 257.6h2.6M262 253.8h6.8M263.7 255.1l-.1 .9 .2 .6M263.7 255.1a1.78 1.78 0 0 1 1.7-1.2 1.78 1.78 0 0 1 1.7 1.2M264 252h2.8M264.5 251.7h1.8M264.6 251.3h1.6M264.6 251h1.6M264.6 250.6h1.5M264.7 250.3h1.4M266.2 257.6h2.6"/>
<path d="M266.2 254.1h2.8M266.3 257.3h2.7M266.3 258h2.6M266.5 258.3h2.7M266.6 258.7h2.9M266.7 254.5h2.4M266.7 256.9h2.4M266.8 259h2.9M267 254.8h2.2M267 256.6h2.5M267.1 256.2h4M267.1 255.2h4"/>
<path d="M267.2 255.9h3.9M267.2 255.5h3.9M267.9 259.4h1.9M267.9 252h1.8M268.3 259.7h1.1M268.4 251.7h1M268.8 251.3h.2M269.2 254.8l1.9 .2v1.4l-1.9 .2-.5 1.2 1.2 1.4-1 1-1.4-1.2-.6 .3-.8-2a1.78 1.78 0 0 0 1-2.2M261.7 260.1h.4M268.7 260.1h.4"/>
</g>
<path d="M81.3 47.5h5.1v15.2h-5.1zM182.9 47.5h5v15.2h-5zM81.3 123.6h5.1v15.3h-5.1zM182.9 123.6h5v15.3h-5zM81.3 199.8h5.1v15.3h-5.1z" fill="none" stroke="#000" stroke-width=".42"/>
<path d="M16.5 18.2h387.3v260.4h-387.3z" fill="none" stroke="#000" stroke-width=".32"/>
<use href="#words"/>
</svg>
